# Generated by FakeRAM 2.0
VERSION 5.7 ;
BUSBITCHARS "[]" ;
PROPERTYDEFINITIONS
  MACRO width INTEGER ;
  MACRO depth INTEGER ;
  MACRO banks INTEGER ;
END PROPERTYDEFINITIONS
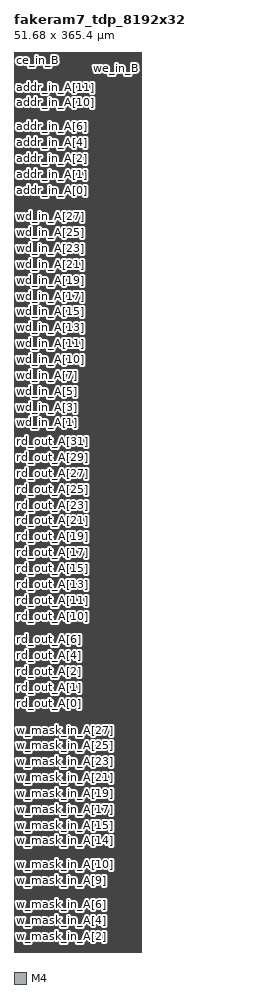
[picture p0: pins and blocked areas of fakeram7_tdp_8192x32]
MACRO fakeram7_tdp_8192x32
  PROPERTY width 32 ;
  PROPERTY depth 8192 ;
  PROPERTY banks 8 ;
  FOREIGN fakeram7_tdp_8192x32 0 0 ;
  SYMMETRY X Y ;
  SIZE 51.680 BY 365.400 ;
  CLASS BLOCK ;
  PIN w_mask_in_A[0]
    DIRECTION INPUT ;
    USE SIGNAL ;
    SHAPE ABUTMENT ;
    PORT
      LAYER M4 ;
      RECT 0.000 0.048 0.024 0.072 ;
    END
  END w_mask_in_A[0]
  PIN w_mask_in_B[0]
    DIRECTION INPUT ;
    USE SIGNAL ;
    SHAPE ABUTMENT ;
    PORT
      LAYER M4 ;
      RECT 51.656 0.048 51.680 0.072 ;
    END
  END w_mask_in_B[0]
  PIN w_mask_in_A[1]
    DIRECTION INPUT ;
    USE SIGNAL ;
    SHAPE ABUTMENT ;
    PORT
      LAYER M4 ;
      RECT 0.000 3.264 0.024 3.288 ;
    END
  END w_mask_in_A[1]
  PIN w_mask_in_B[1]
    DIRECTION INPUT ;
    USE SIGNAL ;
    SHAPE ABUTMENT ;
    PORT
      LAYER M4 ;
      RECT 51.656 3.264 51.680 3.288 ;
    END
  END w_mask_in_B[1]
  PIN w_mask_in_A[2]
    DIRECTION INPUT ;
    USE SIGNAL ;
    SHAPE ABUTMENT ;
    PORT
      LAYER M4 ;
      RECT 0.000 6.480 0.024 6.504 ;
    END
  END w_mask_in_A[2]
  PIN w_mask_in_B[2]
    DIRECTION INPUT ;
    USE SIGNAL ;
    SHAPE ABUTMENT ;
    PORT
      LAYER M4 ;
      RECT 51.656 6.480 51.680 6.504 ;
    END
  END w_mask_in_B[2]
  PIN w_mask_in_A[3]
    DIRECTION INPUT ;
    USE SIGNAL ;
    SHAPE ABUTMENT ;
    PORT
      LAYER M4 ;
      RECT 0.000 9.696 0.024 9.720 ;
    END
  END w_mask_in_A[3]
  PIN w_mask_in_B[3]
    DIRECTION INPUT ;
    USE SIGNAL ;
    SHAPE ABUTMENT ;
    PORT
      LAYER M4 ;
      RECT 51.656 9.696 51.680 9.720 ;
    END
  END w_mask_in_B[3]
  PIN w_mask_in_A[4]
    DIRECTION INPUT ;
    USE SIGNAL ;
    SHAPE ABUTMENT ;
    PORT
      LAYER M4 ;
      RECT 0.000 12.912 0.024 12.936 ;
    END
  END w_mask_in_A[4]
  PIN w_mask_in_B[4]
    DIRECTION INPUT ;
    USE SIGNAL ;
    SHAPE ABUTMENT ;
    PORT
      LAYER M4 ;
      RECT 51.656 12.912 51.680 12.936 ;
    END
  END w_mask_in_B[4]
  PIN w_mask_in_A[5]
    DIRECTION INPUT ;
    USE SIGNAL ;
    SHAPE ABUTMENT ;
    PORT
      LAYER M4 ;
      RECT 0.000 16.128 0.024 16.152 ;
    END
  END w_mask_in_A[5]
  PIN w_mask_in_B[5]
    DIRECTION INPUT ;
    USE SIGNAL ;
    SHAPE ABUTMENT ;
    PORT
      LAYER M4 ;
      RECT 51.656 16.128 51.680 16.152 ;
    END
  END w_mask_in_B[5]
  PIN w_mask_in_A[6]
    DIRECTION INPUT ;
    USE SIGNAL ;
    SHAPE ABUTMENT ;
    PORT
      LAYER M4 ;
      RECT 0.000 19.344 0.024 19.368 ;
    END
  END w_mask_in_A[6]
  PIN w_mask_in_B[6]
    DIRECTION INPUT ;
    USE SIGNAL ;
    SHAPE ABUTMENT ;
    PORT
      LAYER M4 ;
      RECT 51.656 19.344 51.680 19.368 ;
    END
  END w_mask_in_B[6]
  PIN w_mask_in_A[7]
    DIRECTION INPUT ;
    USE SIGNAL ;
    SHAPE ABUTMENT ;
    PORT
      LAYER M4 ;
      RECT 0.000 22.560 0.024 22.584 ;
    END
  END w_mask_in_A[7]
  PIN w_mask_in_B[7]
    DIRECTION INPUT ;
    USE SIGNAL ;
    SHAPE ABUTMENT ;
    PORT
      LAYER M4 ;
      RECT 51.656 22.560 51.680 22.584 ;
    END
  END w_mask_in_B[7]
  PIN w_mask_in_A[8]
    DIRECTION INPUT ;
    USE SIGNAL ;
    SHAPE ABUTMENT ;
    PORT
      LAYER M4 ;
      RECT 0.000 25.776 0.024 25.800 ;
    END
  END w_mask_in_A[8]
  PIN w_mask_in_B[8]
    DIRECTION INPUT ;
    USE SIGNAL ;
    SHAPE ABUTMENT ;
    PORT
      LAYER M4 ;
      RECT 51.656 25.776 51.680 25.800 ;
    END
  END w_mask_in_B[8]
  PIN w_mask_in_A[9]
    DIRECTION INPUT ;
    USE SIGNAL ;
    SHAPE ABUTMENT ;
    PORT
      LAYER M4 ;
      RECT 0.000 28.992 0.024 29.016 ;
    END
  END w_mask_in_A[9]
  PIN w_mask_in_B[9]
    DIRECTION INPUT ;
    USE SIGNAL ;
    SHAPE ABUTMENT ;
    PORT
      LAYER M4 ;
      RECT 51.656 28.992 51.680 29.016 ;
    END
  END w_mask_in_B[9]
  PIN w_mask_in_A[10]
    DIRECTION INPUT ;
    USE SIGNAL ;
    SHAPE ABUTMENT ;
    PORT
      LAYER M4 ;
      RECT 0.000 32.208 0.024 32.232 ;
    END
  END w_mask_in_A[10]
  PIN w_mask_in_B[10]
    DIRECTION INPUT ;
    USE SIGNAL ;
    SHAPE ABUTMENT ;
    PORT
      LAYER M4 ;
      RECT 51.656 32.208 51.680 32.232 ;
    END
  END w_mask_in_B[10]
  PIN w_mask_in_A[11]
    DIRECTION INPUT ;
    USE SIGNAL ;
    SHAPE ABUTMENT ;
    PORT
      LAYER M4 ;
      RECT 0.000 35.424 0.024 35.448 ;
    END
  END w_mask_in_A[11]
  PIN w_mask_in_B[11]
    DIRECTION INPUT ;
    USE SIGNAL ;
    SHAPE ABUTMENT ;
    PORT
      LAYER M4 ;
      RECT 51.656 35.424 51.680 35.448 ;
    END
  END w_mask_in_B[11]
  PIN w_mask_in_A[12]
    DIRECTION INPUT ;
    USE SIGNAL ;
    SHAPE ABUTMENT ;
    PORT
      LAYER M4 ;
      RECT 0.000 38.640 0.024 38.664 ;
    END
  END w_mask_in_A[12]
  PIN w_mask_in_B[12]
    DIRECTION INPUT ;
    USE SIGNAL ;
    SHAPE ABUTMENT ;
    PORT
      LAYER M4 ;
      RECT 51.656 38.640 51.680 38.664 ;
    END
  END w_mask_in_B[12]
  PIN w_mask_in_A[13]
    DIRECTION INPUT ;
    USE SIGNAL ;
    SHAPE ABUTMENT ;
    PORT
      LAYER M4 ;
      RECT 0.000 41.856 0.024 41.880 ;
    END
  END w_mask_in_A[13]
  PIN w_mask_in_B[13]
    DIRECTION INPUT ;
    USE SIGNAL ;
    SHAPE ABUTMENT ;
    PORT
      LAYER M4 ;
      RECT 51.656 41.856 51.680 41.880 ;
    END
  END w_mask_in_B[13]
  PIN w_mask_in_A[14]
    DIRECTION INPUT ;
    USE SIGNAL ;
    SHAPE ABUTMENT ;
    PORT
      LAYER M4 ;
      RECT 0.000 45.072 0.024 45.096 ;
    END
  END w_mask_in_A[14]
  PIN w_mask_in_B[14]
    DIRECTION INPUT ;
    USE SIGNAL ;
    SHAPE ABUTMENT ;
    PORT
      LAYER M4 ;
      RECT 51.656 45.072 51.680 45.096 ;
    END
  END w_mask_in_B[14]
  PIN w_mask_in_A[15]
    DIRECTION INPUT ;
    USE SIGNAL ;
    SHAPE ABUTMENT ;
    PORT
      LAYER M4 ;
      RECT 0.000 48.288 0.024 48.312 ;
    END
  END w_mask_in_A[15]
  PIN w_mask_in_B[15]
    DIRECTION INPUT ;
    USE SIGNAL ;
    SHAPE ABUTMENT ;
    PORT
      LAYER M4 ;
      RECT 51.656 48.288 51.680 48.312 ;
    END
  END w_mask_in_B[15]
  PIN w_mask_in_A[16]
    DIRECTION INPUT ;
    USE SIGNAL ;
    SHAPE ABUTMENT ;
    PORT
      LAYER M4 ;
      RECT 0.000 51.504 0.024 51.528 ;
    END
  END w_mask_in_A[16]
  PIN w_mask_in_B[16]
    DIRECTION INPUT ;
    USE SIGNAL ;
    SHAPE ABUTMENT ;
    PORT
      LAYER M4 ;
      RECT 51.656 51.504 51.680 51.528 ;
    END
  END w_mask_in_B[16]
  PIN w_mask_in_A[17]
    DIRECTION INPUT ;
    USE SIGNAL ;
    SHAPE ABUTMENT ;
    PORT
      LAYER M4 ;
      RECT 0.000 54.720 0.024 54.744 ;
    END
  END w_mask_in_A[17]
  PIN w_mask_in_B[17]
    DIRECTION INPUT ;
    USE SIGNAL ;
    SHAPE ABUTMENT ;
    PORT
      LAYER M4 ;
      RECT 51.656 54.720 51.680 54.744 ;
    END
  END w_mask_in_B[17]
  PIN w_mask_in_A[18]
    DIRECTION INPUT ;
    USE SIGNAL ;
    SHAPE ABUTMENT ;
    PORT
      LAYER M4 ;
      RECT 0.000 57.936 0.024 57.960 ;
    END
  END w_mask_in_A[18]
  PIN w_mask_in_B[18]
    DIRECTION INPUT ;
    USE SIGNAL ;
    SHAPE ABUTMENT ;
    PORT
      LAYER M4 ;
      RECT 51.656 57.936 51.680 57.960 ;
    END
  END w_mask_in_B[18]
  PIN w_mask_in_A[19]
    DIRECTION INPUT ;
    USE SIGNAL ;
    SHAPE ABUTMENT ;
    PORT
      LAYER M4 ;
      RECT 0.000 61.152 0.024 61.176 ;
    END
  END w_mask_in_A[19]
  PIN w_mask_in_B[19]
    DIRECTION INPUT ;
    USE SIGNAL ;
    SHAPE ABUTMENT ;
    PORT
      LAYER M4 ;
      RECT 51.656 61.152 51.680 61.176 ;
    END
  END w_mask_in_B[19]
  PIN w_mask_in_A[20]
    DIRECTION INPUT ;
    USE SIGNAL ;
    SHAPE ABUTMENT ;
    PORT
      LAYER M4 ;
      RECT 0.000 64.368 0.024 64.392 ;
    END
  END w_mask_in_A[20]
  PIN w_mask_in_B[20]
    DIRECTION INPUT ;
    USE SIGNAL ;
    SHAPE ABUTMENT ;
    PORT
      LAYER M4 ;
      RECT 51.656 64.368 51.680 64.392 ;
    END
  END w_mask_in_B[20]
  PIN w_mask_in_A[21]
    DIRECTION INPUT ;
    USE SIGNAL ;
    SHAPE ABUTMENT ;
    PORT
      LAYER M4 ;
      RECT 0.000 67.584 0.024 67.608 ;
    END
  END w_mask_in_A[21]
  PIN w_mask_in_B[21]
    DIRECTION INPUT ;
    USE SIGNAL ;
    SHAPE ABUTMENT ;
    PORT
      LAYER M4 ;
      RECT 51.656 67.584 51.680 67.608 ;
    END
  END w_mask_in_B[21]
  PIN w_mask_in_A[22]
    DIRECTION INPUT ;
    USE SIGNAL ;
    SHAPE ABUTMENT ;
    PORT
      LAYER M4 ;
      RECT 0.000 70.800 0.024 70.824 ;
    END
  END w_mask_in_A[22]
  PIN w_mask_in_B[22]
    DIRECTION INPUT ;
    USE SIGNAL ;
    SHAPE ABUTMENT ;
    PORT
      LAYER M4 ;
      RECT 51.656 70.800 51.680 70.824 ;
    END
  END w_mask_in_B[22]
  PIN w_mask_in_A[23]
    DIRECTION INPUT ;
    USE SIGNAL ;
    SHAPE ABUTMENT ;
    PORT
      LAYER M4 ;
      RECT 0.000 74.016 0.024 74.040 ;
    END
  END w_mask_in_A[23]
  PIN w_mask_in_B[23]
    DIRECTION INPUT ;
    USE SIGNAL ;
    SHAPE ABUTMENT ;
    PORT
      LAYER M4 ;
      RECT 51.656 74.016 51.680 74.040 ;
    END
  END w_mask_in_B[23]
  PIN w_mask_in_A[24]
    DIRECTION INPUT ;
    USE SIGNAL ;
    SHAPE ABUTMENT ;
    PORT
      LAYER M4 ;
      RECT 0.000 77.232 0.024 77.256 ;
    END
  END w_mask_in_A[24]
  PIN w_mask_in_B[24]
    DIRECTION INPUT ;
    USE SIGNAL ;
    SHAPE ABUTMENT ;
    PORT
      LAYER M4 ;
      RECT 51.656 77.232 51.680 77.256 ;
    END
  END w_mask_in_B[24]
  PIN w_mask_in_A[25]
    DIRECTION INPUT ;
    USE SIGNAL ;
    SHAPE ABUTMENT ;
    PORT
      LAYER M4 ;
      RECT 0.000 80.448 0.024 80.472 ;
    END
  END w_mask_in_A[25]
  PIN w_mask_in_B[25]
    DIRECTION INPUT ;
    USE SIGNAL ;
    SHAPE ABUTMENT ;
    PORT
      LAYER M4 ;
      RECT 51.656 80.448 51.680 80.472 ;
    END
  END w_mask_in_B[25]
  PIN w_mask_in_A[26]
    DIRECTION INPUT ;
    USE SIGNAL ;
    SHAPE ABUTMENT ;
    PORT
      LAYER M4 ;
      RECT 0.000 83.664 0.024 83.688 ;
    END
  END w_mask_in_A[26]
  PIN w_mask_in_B[26]
    DIRECTION INPUT ;
    USE SIGNAL ;
    SHAPE ABUTMENT ;
    PORT
      LAYER M4 ;
      RECT 51.656 83.664 51.680 83.688 ;
    END
  END w_mask_in_B[26]
  PIN w_mask_in_A[27]
    DIRECTION INPUT ;
    USE SIGNAL ;
    SHAPE ABUTMENT ;
    PORT
      LAYER M4 ;
      RECT 0.000 86.880 0.024 86.904 ;
    END
  END w_mask_in_A[27]
  PIN w_mask_in_B[27]
    DIRECTION INPUT ;
    USE SIGNAL ;
    SHAPE ABUTMENT ;
    PORT
      LAYER M4 ;
      RECT 51.656 86.880 51.680 86.904 ;
    END
  END w_mask_in_B[27]
  PIN w_mask_in_A[28]
    DIRECTION INPUT ;
    USE SIGNAL ;
    SHAPE ABUTMENT ;
    PORT
      LAYER M4 ;
      RECT 0.000 90.096 0.024 90.120 ;
    END
  END w_mask_in_A[28]
  PIN w_mask_in_B[28]
    DIRECTION INPUT ;
    USE SIGNAL ;
    SHAPE ABUTMENT ;
    PORT
      LAYER M4 ;
      RECT 51.656 90.096 51.680 90.120 ;
    END
  END w_mask_in_B[28]
  PIN w_mask_in_A[29]
    DIRECTION INPUT ;
    USE SIGNAL ;
    SHAPE ABUTMENT ;
    PORT
      LAYER M4 ;
      RECT 0.000 93.312 0.024 93.336 ;
    END
  END w_mask_in_A[29]
  PIN w_mask_in_B[29]
    DIRECTION INPUT ;
    USE SIGNAL ;
    SHAPE ABUTMENT ;
    PORT
      LAYER M4 ;
      RECT 51.656 93.312 51.680 93.336 ;
    END
  END w_mask_in_B[29]
  PIN w_mask_in_A[30]
    DIRECTION INPUT ;
    USE SIGNAL ;
    SHAPE ABUTMENT ;
    PORT
      LAYER M4 ;
      RECT 0.000 96.528 0.024 96.552 ;
    END
  END w_mask_in_A[30]
  PIN w_mask_in_B[30]
    DIRECTION INPUT ;
    USE SIGNAL ;
    SHAPE ABUTMENT ;
    PORT
      LAYER M4 ;
      RECT 51.656 96.528 51.680 96.552 ;
    END
  END w_mask_in_B[30]
  PIN w_mask_in_A[31]
    DIRECTION INPUT ;
    USE SIGNAL ;
    SHAPE ABUTMENT ;
    PORT
      LAYER M4 ;
      RECT 0.000 99.744 0.024 99.768 ;
    END
  END w_mask_in_A[31]
  PIN w_mask_in_B[31]
    DIRECTION INPUT ;
    USE SIGNAL ;
    SHAPE ABUTMENT ;
    PORT
      LAYER M4 ;
      RECT 51.656 99.744 51.680 99.768 ;
    END
  END w_mask_in_B[31]
  PIN rd_out_A[0]
    DIRECTION OUTPUT ;
    USE SIGNAL ;
    SHAPE ABUTMENT ;
    PORT
      LAYER M4 ;
      RECT 0.000 104.208 0.024 104.232 ;
    END
  END rd_out_A[0]
  PIN rd_out_B[0]
    DIRECTION OUTPUT ;
    USE SIGNAL ;
    SHAPE ABUTMENT ;
    PORT
      LAYER M4 ;
      RECT 51.656 104.208 51.680 104.232 ;
    END
  END rd_out_B[0]
  PIN rd_out_A[1]
    DIRECTION OUTPUT ;
    USE SIGNAL ;
    SHAPE ABUTMENT ;
    PORT
      LAYER M4 ;
      RECT 0.000 107.424 0.024 107.448 ;
    END
  END rd_out_A[1]
  PIN rd_out_B[1]
    DIRECTION OUTPUT ;
    USE SIGNAL ;
    SHAPE ABUTMENT ;
    PORT
      LAYER M4 ;
      RECT 51.656 107.424 51.680 107.448 ;
    END
  END rd_out_B[1]
  PIN rd_out_A[2]
    DIRECTION OUTPUT ;
    USE SIGNAL ;
    SHAPE ABUTMENT ;
    PORT
      LAYER M4 ;
      RECT 0.000 110.640 0.024 110.664 ;
    END
  END rd_out_A[2]
  PIN rd_out_B[2]
    DIRECTION OUTPUT ;
    USE SIGNAL ;
    SHAPE ABUTMENT ;
    PORT
      LAYER M4 ;
      RECT 51.656 110.640 51.680 110.664 ;
    END
  END rd_out_B[2]
  PIN rd_out_A[3]
    DIRECTION OUTPUT ;
    USE SIGNAL ;
    SHAPE ABUTMENT ;
    PORT
      LAYER M4 ;
      RECT 0.000 113.856 0.024 113.880 ;
    END
  END rd_out_A[3]
  PIN rd_out_B[3]
    DIRECTION OUTPUT ;
    USE SIGNAL ;
    SHAPE ABUTMENT ;
    PORT
      LAYER M4 ;
      RECT 51.656 113.856 51.680 113.880 ;
    END
  END rd_out_B[3]
  PIN rd_out_A[4]
    DIRECTION OUTPUT ;
    USE SIGNAL ;
    SHAPE ABUTMENT ;
    PORT
      LAYER M4 ;
      RECT 0.000 117.072 0.024 117.096 ;
    END
  END rd_out_A[4]
  PIN rd_out_B[4]
    DIRECTION OUTPUT ;
    USE SIGNAL ;
    SHAPE ABUTMENT ;
    PORT
      LAYER M4 ;
      RECT 51.656 117.072 51.680 117.096 ;
    END
  END rd_out_B[4]
  PIN rd_out_A[5]
    DIRECTION OUTPUT ;
    USE SIGNAL ;
    SHAPE ABUTMENT ;
    PORT
      LAYER M4 ;
      RECT 0.000 120.288 0.024 120.312 ;
    END
  END rd_out_A[5]
  PIN rd_out_B[5]
    DIRECTION OUTPUT ;
    USE SIGNAL ;
    SHAPE ABUTMENT ;
    PORT
      LAYER M4 ;
      RECT 51.656 120.288 51.680 120.312 ;
    END
  END rd_out_B[5]
  PIN rd_out_A[6]
    DIRECTION OUTPUT ;
    USE SIGNAL ;
    SHAPE ABUTMENT ;
    PORT
      LAYER M4 ;
      RECT 0.000 123.504 0.024 123.528 ;
    END
  END rd_out_A[6]
  PIN rd_out_B[6]
    DIRECTION OUTPUT ;
    USE SIGNAL ;
    SHAPE ABUTMENT ;
    PORT
      LAYER M4 ;
      RECT 51.656 123.504 51.680 123.528 ;
    END
  END rd_out_B[6]
  PIN rd_out_A[7]
    DIRECTION OUTPUT ;
    USE SIGNAL ;
    SHAPE ABUTMENT ;
    PORT
      LAYER M4 ;
      RECT 0.000 126.720 0.024 126.744 ;
    END
  END rd_out_A[7]
  PIN rd_out_B[7]
    DIRECTION OUTPUT ;
    USE SIGNAL ;
    SHAPE ABUTMENT ;
    PORT
      LAYER M4 ;
      RECT 51.656 126.720 51.680 126.744 ;
    END
  END rd_out_B[7]
  PIN rd_out_A[8]
    DIRECTION OUTPUT ;
    USE SIGNAL ;
    SHAPE ABUTMENT ;
    PORT
      LAYER M4 ;
      RECT 0.000 129.936 0.024 129.960 ;
    END
  END rd_out_A[8]
  PIN rd_out_B[8]
    DIRECTION OUTPUT ;
    USE SIGNAL ;
    SHAPE ABUTMENT ;
    PORT
      LAYER M4 ;
      RECT 51.656 129.936 51.680 129.960 ;
    END
  END rd_out_B[8]
  PIN rd_out_A[9]
    DIRECTION OUTPUT ;
    USE SIGNAL ;
    SHAPE ABUTMENT ;
    PORT
      LAYER M4 ;
      RECT 0.000 133.152 0.024 133.176 ;
    END
  END rd_out_A[9]
  PIN rd_out_B[9]
    DIRECTION OUTPUT ;
    USE SIGNAL ;
    SHAPE ABUTMENT ;
    PORT
      LAYER M4 ;
      RECT 51.656 133.152 51.680 133.176 ;
    END
  END rd_out_B[9]
  PIN rd_out_A[10]
    DIRECTION OUTPUT ;
    USE SIGNAL ;
    SHAPE ABUTMENT ;
    PORT
      LAYER M4 ;
      RECT 0.000 136.368 0.024 136.392 ;
    END
  END rd_out_A[10]
  PIN rd_out_B[10]
    DIRECTION OUTPUT ;
    USE SIGNAL ;
    SHAPE ABUTMENT ;
    PORT
      LAYER M4 ;
      RECT 51.656 136.368 51.680 136.392 ;
    END
  END rd_out_B[10]
  PIN rd_out_A[11]
    DIRECTION OUTPUT ;
    USE SIGNAL ;
    SHAPE ABUTMENT ;
    PORT
      LAYER M4 ;
      RECT 0.000 139.584 0.024 139.608 ;
    END
  END rd_out_A[11]
  PIN rd_out_B[11]
    DIRECTION OUTPUT ;
    USE SIGNAL ;
    SHAPE ABUTMENT ;
    PORT
      LAYER M4 ;
      RECT 51.656 139.584 51.680 139.608 ;
    END
  END rd_out_B[11]
  PIN rd_out_A[12]
    DIRECTION OUTPUT ;
    USE SIGNAL ;
    SHAPE ABUTMENT ;
    PORT
      LAYER M4 ;
      RECT 0.000 142.800 0.024 142.824 ;
    END
  END rd_out_A[12]
  PIN rd_out_B[12]
    DIRECTION OUTPUT ;
    USE SIGNAL ;
    SHAPE ABUTMENT ;
    PORT
      LAYER M4 ;
      RECT 51.656 142.800 51.680 142.824 ;
    END
  END rd_out_B[12]
  PIN rd_out_A[13]
    DIRECTION OUTPUT ;
    USE SIGNAL ;
    SHAPE ABUTMENT ;
    PORT
      LAYER M4 ;
      RECT 0.000 146.016 0.024 146.040 ;
    END
  END rd_out_A[13]
  PIN rd_out_B[13]
    DIRECTION OUTPUT ;
    USE SIGNAL ;
    SHAPE ABUTMENT ;
    PORT
      LAYER M4 ;
      RECT 51.656 146.016 51.680 146.040 ;
    END
  END rd_out_B[13]
  PIN rd_out_A[14]
    DIRECTION OUTPUT ;
    USE SIGNAL ;
    SHAPE ABUTMENT ;
    PORT
      LAYER M4 ;
      RECT 0.000 149.232 0.024 149.256 ;
    END
  END rd_out_A[14]
  PIN rd_out_B[14]
    DIRECTION OUTPUT ;
    USE SIGNAL ;
    SHAPE ABUTMENT ;
    PORT
      LAYER M4 ;
      RECT 51.656 149.232 51.680 149.256 ;
    END
  END rd_out_B[14]
  PIN rd_out_A[15]
    DIRECTION OUTPUT ;
    USE SIGNAL ;
    SHAPE ABUTMENT ;
    PORT
      LAYER M4 ;
      RECT 0.000 152.448 0.024 152.472 ;
    END
  END rd_out_A[15]
  PIN rd_out_B[15]
    DIRECTION OUTPUT ;
    USE SIGNAL ;
    SHAPE ABUTMENT ;
    PORT
      LAYER M4 ;
      RECT 51.656 152.448 51.680 152.472 ;
    END
  END rd_out_B[15]
  PIN rd_out_A[16]
    DIRECTION OUTPUT ;
    USE SIGNAL ;
    SHAPE ABUTMENT ;
    PORT
      LAYER M4 ;
      RECT 0.000 155.664 0.024 155.688 ;
    END
  END rd_out_A[16]
  PIN rd_out_B[16]
    DIRECTION OUTPUT ;
    USE SIGNAL ;
    SHAPE ABUTMENT ;
    PORT
      LAYER M4 ;
      RECT 51.656 155.664 51.680 155.688 ;
    END
  END rd_out_B[16]
  PIN rd_out_A[17]
    DIRECTION OUTPUT ;
    USE SIGNAL ;
    SHAPE ABUTMENT ;
    PORT
      LAYER M4 ;
      RECT 0.000 158.880 0.024 158.904 ;
    END
  END rd_out_A[17]
  PIN rd_out_B[17]
    DIRECTION OUTPUT ;
    USE SIGNAL ;
    SHAPE ABUTMENT ;
    PORT
      LAYER M4 ;
      RECT 51.656 158.880 51.680 158.904 ;
    END
  END rd_out_B[17]
  PIN rd_out_A[18]
    DIRECTION OUTPUT ;
    USE SIGNAL ;
    SHAPE ABUTMENT ;
    PORT
      LAYER M4 ;
      RECT 0.000 162.096 0.024 162.120 ;
    END
  END rd_out_A[18]
  PIN rd_out_B[18]
    DIRECTION OUTPUT ;
    USE SIGNAL ;
    SHAPE ABUTMENT ;
    PORT
      LAYER M4 ;
      RECT 51.656 162.096 51.680 162.120 ;
    END
  END rd_out_B[18]
  PIN rd_out_A[19]
    DIRECTION OUTPUT ;
    USE SIGNAL ;
    SHAPE ABUTMENT ;
    PORT
      LAYER M4 ;
      RECT 0.000 165.312 0.024 165.336 ;
    END
  END rd_out_A[19]
  PIN rd_out_B[19]
    DIRECTION OUTPUT ;
    USE SIGNAL ;
    SHAPE ABUTMENT ;
    PORT
      LAYER M4 ;
      RECT 51.656 165.312 51.680 165.336 ;
    END
  END rd_out_B[19]
  PIN rd_out_A[20]
    DIRECTION OUTPUT ;
    USE SIGNAL ;
    SHAPE ABUTMENT ;
    PORT
      LAYER M4 ;
      RECT 0.000 168.528 0.024 168.552 ;
    END
  END rd_out_A[20]
  PIN rd_out_B[20]
    DIRECTION OUTPUT ;
    USE SIGNAL ;
    SHAPE ABUTMENT ;
    PORT
      LAYER M4 ;
      RECT 51.656 168.528 51.680 168.552 ;
    END
  END rd_out_B[20]
  PIN rd_out_A[21]
    DIRECTION OUTPUT ;
    USE SIGNAL ;
    SHAPE ABUTMENT ;
    PORT
      LAYER M4 ;
      RECT 0.000 171.744 0.024 171.768 ;
    END
  END rd_out_A[21]
  PIN rd_out_B[21]
    DIRECTION OUTPUT ;
    USE SIGNAL ;
    SHAPE ABUTMENT ;
    PORT
      LAYER M4 ;
      RECT 51.656 171.744 51.680 171.768 ;
    END
  END rd_out_B[21]
  PIN rd_out_A[22]
    DIRECTION OUTPUT ;
    USE SIGNAL ;
    SHAPE ABUTMENT ;
    PORT
      LAYER M4 ;
      RECT 0.000 174.960 0.024 174.984 ;
    END
  END rd_out_A[22]
  PIN rd_out_B[22]
    DIRECTION OUTPUT ;
    USE SIGNAL ;
    SHAPE ABUTMENT ;
    PORT
      LAYER M4 ;
      RECT 51.656 174.960 51.680 174.984 ;
    END
  END rd_out_B[22]
  PIN rd_out_A[23]
    DIRECTION OUTPUT ;
    USE SIGNAL ;
    SHAPE ABUTMENT ;
    PORT
      LAYER M4 ;
      RECT 0.000 178.176 0.024 178.200 ;
    END
  END rd_out_A[23]
  PIN rd_out_B[23]
    DIRECTION OUTPUT ;
    USE SIGNAL ;
    SHAPE ABUTMENT ;
    PORT
      LAYER M4 ;
      RECT 51.656 178.176 51.680 178.200 ;
    END
  END rd_out_B[23]
  PIN rd_out_A[24]
    DIRECTION OUTPUT ;
    USE SIGNAL ;
    SHAPE ABUTMENT ;
    PORT
      LAYER M4 ;
      RECT 0.000 181.392 0.024 181.416 ;
    END
  END rd_out_A[24]
  PIN rd_out_B[24]
    DIRECTION OUTPUT ;
    USE SIGNAL ;
    SHAPE ABUTMENT ;
    PORT
      LAYER M4 ;
      RECT 51.656 181.392 51.680 181.416 ;
    END
  END rd_out_B[24]
  PIN rd_out_A[25]
    DIRECTION OUTPUT ;
    USE SIGNAL ;
    SHAPE ABUTMENT ;
    PORT
      LAYER M4 ;
      RECT 0.000 184.608 0.024 184.632 ;
    END
  END rd_out_A[25]
  PIN rd_out_B[25]
    DIRECTION OUTPUT ;
    USE SIGNAL ;
    SHAPE ABUTMENT ;
    PORT
      LAYER M4 ;
      RECT 51.656 184.608 51.680 184.632 ;
    END
  END rd_out_B[25]
  PIN rd_out_A[26]
    DIRECTION OUTPUT ;
    USE SIGNAL ;
    SHAPE ABUTMENT ;
    PORT
      LAYER M4 ;
      RECT 0.000 187.824 0.024 187.848 ;
    END
  END rd_out_A[26]
  PIN rd_out_B[26]
    DIRECTION OUTPUT ;
    USE SIGNAL ;
    SHAPE ABUTMENT ;
    PORT
      LAYER M4 ;
      RECT 51.656 187.824 51.680 187.848 ;
    END
  END rd_out_B[26]
  PIN rd_out_A[27]
    DIRECTION OUTPUT ;
    USE SIGNAL ;
    SHAPE ABUTMENT ;
    PORT
      LAYER M4 ;
      RECT 0.000 191.040 0.024 191.064 ;
    END
  END rd_out_A[27]
  PIN rd_out_B[27]
    DIRECTION OUTPUT ;
    USE SIGNAL ;
    SHAPE ABUTMENT ;
    PORT
      LAYER M4 ;
      RECT 51.656 191.040 51.680 191.064 ;
    END
  END rd_out_B[27]
  PIN rd_out_A[28]
    DIRECTION OUTPUT ;
    USE SIGNAL ;
    SHAPE ABUTMENT ;
    PORT
      LAYER M4 ;
      RECT 0.000 194.256 0.024 194.280 ;
    END
  END rd_out_A[28]
  PIN rd_out_B[28]
    DIRECTION OUTPUT ;
    USE SIGNAL ;
    SHAPE ABUTMENT ;
    PORT
      LAYER M4 ;
      RECT 51.656 194.256 51.680 194.280 ;
    END
  END rd_out_B[28]
  PIN rd_out_A[29]
    DIRECTION OUTPUT ;
    USE SIGNAL ;
    SHAPE ABUTMENT ;
    PORT
      LAYER M4 ;
      RECT 0.000 197.472 0.024 197.496 ;
    END
  END rd_out_A[29]
  PIN rd_out_B[29]
    DIRECTION OUTPUT ;
    USE SIGNAL ;
    SHAPE ABUTMENT ;
    PORT
      LAYER M4 ;
      RECT 51.656 197.472 51.680 197.496 ;
    END
  END rd_out_B[29]
  PIN rd_out_A[30]
    DIRECTION OUTPUT ;
    USE SIGNAL ;
    SHAPE ABUTMENT ;
    PORT
      LAYER M4 ;
      RECT 0.000 200.688 0.024 200.712 ;
    END
  END rd_out_A[30]
  PIN rd_out_B[30]
    DIRECTION OUTPUT ;
    USE SIGNAL ;
    SHAPE ABUTMENT ;
    PORT
      LAYER M4 ;
      RECT 51.656 200.688 51.680 200.712 ;
    END
  END rd_out_B[30]
  PIN rd_out_A[31]
    DIRECTION OUTPUT ;
    USE SIGNAL ;
    SHAPE ABUTMENT ;
    PORT
      LAYER M4 ;
      RECT 0.000 203.904 0.024 203.928 ;
    END
  END rd_out_A[31]
  PIN rd_out_B[31]
    DIRECTION OUTPUT ;
    USE SIGNAL ;
    SHAPE ABUTMENT ;
    PORT
      LAYER M4 ;
      RECT 51.656 203.904 51.680 203.928 ;
    END
  END rd_out_B[31]
  PIN wd_in_A[0]
    DIRECTION INPUT ;
    USE SIGNAL ;
    SHAPE ABUTMENT ;
    PORT
      LAYER M4 ;
      RECT 0.000 208.368 0.024 208.392 ;
    END
  END wd_in_A[0]
  PIN wd_in_B[0]
    DIRECTION INPUT ;
    USE SIGNAL ;
    SHAPE ABUTMENT ;
    PORT
      LAYER M4 ;
      RECT 51.656 208.368 51.680 208.392 ;
    END
  END wd_in_B[0]
  PIN wd_in_A[1]
    DIRECTION INPUT ;
    USE SIGNAL ;
    SHAPE ABUTMENT ;
    PORT
      LAYER M4 ;
      RECT 0.000 211.584 0.024 211.608 ;
    END
  END wd_in_A[1]
  PIN wd_in_B[1]
    DIRECTION INPUT ;
    USE SIGNAL ;
    SHAPE ABUTMENT ;
    PORT
      LAYER M4 ;
      RECT 51.656 211.584 51.680 211.608 ;
    END
  END wd_in_B[1]
  PIN wd_in_A[2]
    DIRECTION INPUT ;
    USE SIGNAL ;
    SHAPE ABUTMENT ;
    PORT
      LAYER M4 ;
      RECT 0.000 214.800 0.024 214.824 ;
    END
  END wd_in_A[2]
  PIN wd_in_B[2]
    DIRECTION INPUT ;
    USE SIGNAL ;
    SHAPE ABUTMENT ;
    PORT
      LAYER M4 ;
      RECT 51.656 214.800 51.680 214.824 ;
    END
  END wd_in_B[2]
  PIN wd_in_A[3]
    DIRECTION INPUT ;
    USE SIGNAL ;
    SHAPE ABUTMENT ;
    PORT
      LAYER M4 ;
      RECT 0.000 218.016 0.024 218.040 ;
    END
  END wd_in_A[3]
  PIN wd_in_B[3]
    DIRECTION INPUT ;
    USE SIGNAL ;
    SHAPE ABUTMENT ;
    PORT
      LAYER M4 ;
      RECT 51.656 218.016 51.680 218.040 ;
    END
  END wd_in_B[3]
  PIN wd_in_A[4]
    DIRECTION INPUT ;
    USE SIGNAL ;
    SHAPE ABUTMENT ;
    PORT
      LAYER M4 ;
      RECT 0.000 221.232 0.024 221.256 ;
    END
  END wd_in_A[4]
  PIN wd_in_B[4]
    DIRECTION INPUT ;
    USE SIGNAL ;
    SHAPE ABUTMENT ;
    PORT
      LAYER M4 ;
      RECT 51.656 221.232 51.680 221.256 ;
    END
  END wd_in_B[4]
  PIN wd_in_A[5]
    DIRECTION INPUT ;
    USE SIGNAL ;
    SHAPE ABUTMENT ;
    PORT
      LAYER M4 ;
      RECT 0.000 224.448 0.024 224.472 ;
    END
  END wd_in_A[5]
  PIN wd_in_B[5]
    DIRECTION INPUT ;
    USE SIGNAL ;
    SHAPE ABUTMENT ;
    PORT
      LAYER M4 ;
      RECT 51.656 224.448 51.680 224.472 ;
    END
  END wd_in_B[5]
  PIN wd_in_A[6]
    DIRECTION INPUT ;
    USE SIGNAL ;
    SHAPE ABUTMENT ;
    PORT
      LAYER M4 ;
      RECT 0.000 227.664 0.024 227.688 ;
    END
  END wd_in_A[6]
  PIN wd_in_B[6]
    DIRECTION INPUT ;
    USE SIGNAL ;
    SHAPE ABUTMENT ;
    PORT
      LAYER M4 ;
      RECT 51.656 227.664 51.680 227.688 ;
    END
  END wd_in_B[6]
  PIN wd_in_A[7]
    DIRECTION INPUT ;
    USE SIGNAL ;
    SHAPE ABUTMENT ;
    PORT
      LAYER M4 ;
      RECT 0.000 230.880 0.024 230.904 ;
    END
  END wd_in_A[7]
  PIN wd_in_B[7]
    DIRECTION INPUT ;
    USE SIGNAL ;
    SHAPE ABUTMENT ;
    PORT
      LAYER M4 ;
      RECT 51.656 230.880 51.680 230.904 ;
    END
  END wd_in_B[7]
  PIN wd_in_A[8]
    DIRECTION INPUT ;
    USE SIGNAL ;
    SHAPE ABUTMENT ;
    PORT
      LAYER M4 ;
      RECT 0.000 234.096 0.024 234.120 ;
    END
  END wd_in_A[8]
  PIN wd_in_B[8]
    DIRECTION INPUT ;
    USE SIGNAL ;
    SHAPE ABUTMENT ;
    PORT
      LAYER M4 ;
      RECT 51.656 234.096 51.680 234.120 ;
    END
  END wd_in_B[8]
  PIN wd_in_A[9]
    DIRECTION INPUT ;
    USE SIGNAL ;
    SHAPE ABUTMENT ;
    PORT
      LAYER M4 ;
      RECT 0.000 237.312 0.024 237.336 ;
    END
  END wd_in_A[9]
  PIN wd_in_B[9]
    DIRECTION INPUT ;
    USE SIGNAL ;
    SHAPE ABUTMENT ;
    PORT
      LAYER M4 ;
      RECT 51.656 237.312 51.680 237.336 ;
    END
  END wd_in_B[9]
  PIN wd_in_A[10]
    DIRECTION INPUT ;
    USE SIGNAL ;
    SHAPE ABUTMENT ;
    PORT
      LAYER M4 ;
      RECT 0.000 240.528 0.024 240.552 ;
    END
  END wd_in_A[10]
  PIN wd_in_B[10]
    DIRECTION INPUT ;
    USE SIGNAL ;
    SHAPE ABUTMENT ;
    PORT
      LAYER M4 ;
      RECT 51.656 240.528 51.680 240.552 ;
    END
  END wd_in_B[10]
  PIN wd_in_A[11]
    DIRECTION INPUT ;
    USE SIGNAL ;
    SHAPE ABUTMENT ;
    PORT
      LAYER M4 ;
      RECT 0.000 243.744 0.024 243.768 ;
    END
  END wd_in_A[11]
  PIN wd_in_B[11]
    DIRECTION INPUT ;
    USE SIGNAL ;
    SHAPE ABUTMENT ;
    PORT
      LAYER M4 ;
      RECT 51.656 243.744 51.680 243.768 ;
    END
  END wd_in_B[11]
  PIN wd_in_A[12]
    DIRECTION INPUT ;
    USE SIGNAL ;
    SHAPE ABUTMENT ;
    PORT
      LAYER M4 ;
      RECT 0.000 246.960 0.024 246.984 ;
    END
  END wd_in_A[12]
  PIN wd_in_B[12]
    DIRECTION INPUT ;
    USE SIGNAL ;
    SHAPE ABUTMENT ;
    PORT
      LAYER M4 ;
      RECT 51.656 246.960 51.680 246.984 ;
    END
  END wd_in_B[12]
  PIN wd_in_A[13]
    DIRECTION INPUT ;
    USE SIGNAL ;
    SHAPE ABUTMENT ;
    PORT
      LAYER M4 ;
      RECT 0.000 250.176 0.024 250.200 ;
    END
  END wd_in_A[13]
  PIN wd_in_B[13]
    DIRECTION INPUT ;
    USE SIGNAL ;
    SHAPE ABUTMENT ;
    PORT
      LAYER M4 ;
      RECT 51.656 250.176 51.680 250.200 ;
    END
  END wd_in_B[13]
  PIN wd_in_A[14]
    DIRECTION INPUT ;
    USE SIGNAL ;
    SHAPE ABUTMENT ;
    PORT
      LAYER M4 ;
      RECT 0.000 253.392 0.024 253.416 ;
    END
  END wd_in_A[14]
  PIN wd_in_B[14]
    DIRECTION INPUT ;
    USE SIGNAL ;
    SHAPE ABUTMENT ;
    PORT
      LAYER M4 ;
      RECT 51.656 253.392 51.680 253.416 ;
    END
  END wd_in_B[14]
  PIN wd_in_A[15]
    DIRECTION INPUT ;
    USE SIGNAL ;
    SHAPE ABUTMENT ;
    PORT
      LAYER M4 ;
      RECT 0.000 256.608 0.024 256.632 ;
    END
  END wd_in_A[15]
  PIN wd_in_B[15]
    DIRECTION INPUT ;
    USE SIGNAL ;
    SHAPE ABUTMENT ;
    PORT
      LAYER M4 ;
      RECT 51.656 256.608 51.680 256.632 ;
    END
  END wd_in_B[15]
  PIN wd_in_A[16]
    DIRECTION INPUT ;
    USE SIGNAL ;
    SHAPE ABUTMENT ;
    PORT
      LAYER M4 ;
      RECT 0.000 259.824 0.024 259.848 ;
    END
  END wd_in_A[16]
  PIN wd_in_B[16]
    DIRECTION INPUT ;
    USE SIGNAL ;
    SHAPE ABUTMENT ;
    PORT
      LAYER M4 ;
      RECT 51.656 259.824 51.680 259.848 ;
    END
  END wd_in_B[16]
  PIN wd_in_A[17]
    DIRECTION INPUT ;
    USE SIGNAL ;
    SHAPE ABUTMENT ;
    PORT
      LAYER M4 ;
      RECT 0.000 263.040 0.024 263.064 ;
    END
  END wd_in_A[17]
  PIN wd_in_B[17]
    DIRECTION INPUT ;
    USE SIGNAL ;
    SHAPE ABUTMENT ;
    PORT
      LAYER M4 ;
      RECT 51.656 263.040 51.680 263.064 ;
    END
  END wd_in_B[17]
  PIN wd_in_A[18]
    DIRECTION INPUT ;
    USE SIGNAL ;
    SHAPE ABUTMENT ;
    PORT
      LAYER M4 ;
      RECT 0.000 266.256 0.024 266.280 ;
    END
  END wd_in_A[18]
  PIN wd_in_B[18]
    DIRECTION INPUT ;
    USE SIGNAL ;
    SHAPE ABUTMENT ;
    PORT
      LAYER M4 ;
      RECT 51.656 266.256 51.680 266.280 ;
    END
  END wd_in_B[18]
  PIN wd_in_A[19]
    DIRECTION INPUT ;
    USE SIGNAL ;
    SHAPE ABUTMENT ;
    PORT
      LAYER M4 ;
      RECT 0.000 269.472 0.024 269.496 ;
    END
  END wd_in_A[19]
  PIN wd_in_B[19]
    DIRECTION INPUT ;
    USE SIGNAL ;
    SHAPE ABUTMENT ;
    PORT
      LAYER M4 ;
      RECT 51.656 269.472 51.680 269.496 ;
    END
  END wd_in_B[19]
  PIN wd_in_A[20]
    DIRECTION INPUT ;
    USE SIGNAL ;
    SHAPE ABUTMENT ;
    PORT
      LAYER M4 ;
      RECT 0.000 272.688 0.024 272.712 ;
    END
  END wd_in_A[20]
  PIN wd_in_B[20]
    DIRECTION INPUT ;
    USE SIGNAL ;
    SHAPE ABUTMENT ;
    PORT
      LAYER M4 ;
      RECT 51.656 272.688 51.680 272.712 ;
    END
  END wd_in_B[20]
  PIN wd_in_A[21]
    DIRECTION INPUT ;
    USE SIGNAL ;
    SHAPE ABUTMENT ;
    PORT
      LAYER M4 ;
      RECT 0.000 275.904 0.024 275.928 ;
    END
  END wd_in_A[21]
  PIN wd_in_B[21]
    DIRECTION INPUT ;
    USE SIGNAL ;
    SHAPE ABUTMENT ;
    PORT
      LAYER M4 ;
      RECT 51.656 275.904 51.680 275.928 ;
    END
  END wd_in_B[21]
  PIN wd_in_A[22]
    DIRECTION INPUT ;
    USE SIGNAL ;
    SHAPE ABUTMENT ;
    PORT
      LAYER M4 ;
      RECT 0.000 279.120 0.024 279.144 ;
    END
  END wd_in_A[22]
  PIN wd_in_B[22]
    DIRECTION INPUT ;
    USE SIGNAL ;
    SHAPE ABUTMENT ;
    PORT
      LAYER M4 ;
      RECT 51.656 279.120 51.680 279.144 ;
    END
  END wd_in_B[22]
  PIN wd_in_A[23]
    DIRECTION INPUT ;
    USE SIGNAL ;
    SHAPE ABUTMENT ;
    PORT
      LAYER M4 ;
      RECT 0.000 282.336 0.024 282.360 ;
    END
  END wd_in_A[23]
  PIN wd_in_B[23]
    DIRECTION INPUT ;
    USE SIGNAL ;
    SHAPE ABUTMENT ;
    PORT
      LAYER M4 ;
      RECT 51.656 282.336 51.680 282.360 ;
    END
  END wd_in_B[23]
  PIN wd_in_A[24]
    DIRECTION INPUT ;
    USE SIGNAL ;
    SHAPE ABUTMENT ;
    PORT
      LAYER M4 ;
      RECT 0.000 285.552 0.024 285.576 ;
    END
  END wd_in_A[24]
  PIN wd_in_B[24]
    DIRECTION INPUT ;
    USE SIGNAL ;
    SHAPE ABUTMENT ;
    PORT
      LAYER M4 ;
      RECT 51.656 285.552 51.680 285.576 ;
    END
  END wd_in_B[24]
  PIN wd_in_A[25]
    DIRECTION INPUT ;
    USE SIGNAL ;
    SHAPE ABUTMENT ;
    PORT
      LAYER M4 ;
      RECT 0.000 288.768 0.024 288.792 ;
    END
  END wd_in_A[25]
  PIN wd_in_B[25]
    DIRECTION INPUT ;
    USE SIGNAL ;
    SHAPE ABUTMENT ;
    PORT
      LAYER M4 ;
      RECT 51.656 288.768 51.680 288.792 ;
    END
  END wd_in_B[25]
  PIN wd_in_A[26]
    DIRECTION INPUT ;
    USE SIGNAL ;
    SHAPE ABUTMENT ;
    PORT
      LAYER M4 ;
      RECT 0.000 291.984 0.024 292.008 ;
    END
  END wd_in_A[26]
  PIN wd_in_B[26]
    DIRECTION INPUT ;
    USE SIGNAL ;
    SHAPE ABUTMENT ;
    PORT
      LAYER M4 ;
      RECT 51.656 291.984 51.680 292.008 ;
    END
  END wd_in_B[26]
  PIN wd_in_A[27]
    DIRECTION INPUT ;
    USE SIGNAL ;
    SHAPE ABUTMENT ;
    PORT
      LAYER M4 ;
      RECT 0.000 295.200 0.024 295.224 ;
    END
  END wd_in_A[27]
  PIN wd_in_B[27]
    DIRECTION INPUT ;
    USE SIGNAL ;
    SHAPE ABUTMENT ;
    PORT
      LAYER M4 ;
      RECT 51.656 295.200 51.680 295.224 ;
    END
  END wd_in_B[27]
  PIN wd_in_A[28]
    DIRECTION INPUT ;
    USE SIGNAL ;
    SHAPE ABUTMENT ;
    PORT
      LAYER M4 ;
      RECT 0.000 298.416 0.024 298.440 ;
    END
  END wd_in_A[28]
  PIN wd_in_B[28]
    DIRECTION INPUT ;
    USE SIGNAL ;
    SHAPE ABUTMENT ;
    PORT
      LAYER M4 ;
      RECT 51.656 298.416 51.680 298.440 ;
    END
  END wd_in_B[28]
  PIN wd_in_A[29]
    DIRECTION INPUT ;
    USE SIGNAL ;
    SHAPE ABUTMENT ;
    PORT
      LAYER M4 ;
      RECT 0.000 301.632 0.024 301.656 ;
    END
  END wd_in_A[29]
  PIN wd_in_B[29]
    DIRECTION INPUT ;
    USE SIGNAL ;
    SHAPE ABUTMENT ;
    PORT
      LAYER M4 ;
      RECT 51.656 301.632 51.680 301.656 ;
    END
  END wd_in_B[29]
  PIN wd_in_A[30]
    DIRECTION INPUT ;
    USE SIGNAL ;
    SHAPE ABUTMENT ;
    PORT
      LAYER M4 ;
      RECT 0.000 304.848 0.024 304.872 ;
    END
  END wd_in_A[30]
  PIN wd_in_B[30]
    DIRECTION INPUT ;
    USE SIGNAL ;
    SHAPE ABUTMENT ;
    PORT
      LAYER M4 ;
      RECT 51.656 304.848 51.680 304.872 ;
    END
  END wd_in_B[30]
  PIN wd_in_A[31]
    DIRECTION INPUT ;
    USE SIGNAL ;
    SHAPE ABUTMENT ;
    PORT
      LAYER M4 ;
      RECT 0.000 308.064 0.024 308.088 ;
    END
  END wd_in_A[31]
  PIN wd_in_B[31]
    DIRECTION INPUT ;
    USE SIGNAL ;
    SHAPE ABUTMENT ;
    PORT
      LAYER M4 ;
      RECT 51.656 308.064 51.680 308.088 ;
    END
  END wd_in_B[31]
  PIN addr_in_A[0]
    DIRECTION INPUT ;
    USE SIGNAL ;
    SHAPE ABUTMENT ;
    PORT
      LAYER M4 ;
      RECT 0.000 312.528 0.024 312.552 ;
    END
  END addr_in_A[0]
  PIN addr_in_B[0]
    DIRECTION INPUT ;
    USE SIGNAL ;
    SHAPE ABUTMENT ;
    PORT
      LAYER M4 ;
      RECT 51.656 312.528 51.680 312.552 ;
    END
  END addr_in_B[0]
  PIN addr_in_A[1]
    DIRECTION INPUT ;
    USE SIGNAL ;
    SHAPE ABUTMENT ;
    PORT
      LAYER M4 ;
      RECT 0.000 315.744 0.024 315.768 ;
    END
  END addr_in_A[1]
  PIN addr_in_B[1]
    DIRECTION INPUT ;
    USE SIGNAL ;
    SHAPE ABUTMENT ;
    PORT
      LAYER M4 ;
      RECT 51.656 315.744 51.680 315.768 ;
    END
  END addr_in_B[1]
  PIN addr_in_A[2]
    DIRECTION INPUT ;
    USE SIGNAL ;
    SHAPE ABUTMENT ;
    PORT
      LAYER M4 ;
      RECT 0.000 318.960 0.024 318.984 ;
    END
  END addr_in_A[2]
  PIN addr_in_B[2]
    DIRECTION INPUT ;
    USE SIGNAL ;
    SHAPE ABUTMENT ;
    PORT
      LAYER M4 ;
      RECT 51.656 318.960 51.680 318.984 ;
    END
  END addr_in_B[2]
  PIN addr_in_A[3]
    DIRECTION INPUT ;
    USE SIGNAL ;
    SHAPE ABUTMENT ;
    PORT
      LAYER M4 ;
      RECT 0.000 322.176 0.024 322.200 ;
    END
  END addr_in_A[3]
  PIN addr_in_B[3]
    DIRECTION INPUT ;
    USE SIGNAL ;
    SHAPE ABUTMENT ;
    PORT
      LAYER M4 ;
      RECT 51.656 322.176 51.680 322.200 ;
    END
  END addr_in_B[3]
  PIN addr_in_A[4]
    DIRECTION INPUT ;
    USE SIGNAL ;
    SHAPE ABUTMENT ;
    PORT
      LAYER M4 ;
      RECT 0.000 325.392 0.024 325.416 ;
    END
  END addr_in_A[4]
  PIN addr_in_B[4]
    DIRECTION INPUT ;
    USE SIGNAL ;
    SHAPE ABUTMENT ;
    PORT
      LAYER M4 ;
      RECT 51.656 325.392 51.680 325.416 ;
    END
  END addr_in_B[4]
  PIN addr_in_A[5]
    DIRECTION INPUT ;
    USE SIGNAL ;
    SHAPE ABUTMENT ;
    PORT
      LAYER M4 ;
      RECT 0.000 328.608 0.024 328.632 ;
    END
  END addr_in_A[5]
  PIN addr_in_B[5]
    DIRECTION INPUT ;
    USE SIGNAL ;
    SHAPE ABUTMENT ;
    PORT
      LAYER M4 ;
      RECT 51.656 328.608 51.680 328.632 ;
    END
  END addr_in_B[5]
  PIN addr_in_A[6]
    DIRECTION INPUT ;
    USE SIGNAL ;
    SHAPE ABUTMENT ;
    PORT
      LAYER M4 ;
      RECT 0.000 331.824 0.024 331.848 ;
    END
  END addr_in_A[6]
  PIN addr_in_B[6]
    DIRECTION INPUT ;
    USE SIGNAL ;
    SHAPE ABUTMENT ;
    PORT
      LAYER M4 ;
      RECT 51.656 331.824 51.680 331.848 ;
    END
  END addr_in_B[6]
  PIN addr_in_A[7]
    DIRECTION INPUT ;
    USE SIGNAL ;
    SHAPE ABUTMENT ;
    PORT
      LAYER M4 ;
      RECT 0.000 335.040 0.024 335.064 ;
    END
  END addr_in_A[7]
  PIN addr_in_B[7]
    DIRECTION INPUT ;
    USE SIGNAL ;
    SHAPE ABUTMENT ;
    PORT
      LAYER M4 ;
      RECT 51.656 335.040 51.680 335.064 ;
    END
  END addr_in_B[7]
  PIN addr_in_A[8]
    DIRECTION INPUT ;
    USE SIGNAL ;
    SHAPE ABUTMENT ;
    PORT
      LAYER M4 ;
      RECT 0.000 338.256 0.024 338.280 ;
    END
  END addr_in_A[8]
  PIN addr_in_B[8]
    DIRECTION INPUT ;
    USE SIGNAL ;
    SHAPE ABUTMENT ;
    PORT
      LAYER M4 ;
      RECT 51.656 338.256 51.680 338.280 ;
    END
  END addr_in_B[8]
  PIN addr_in_A[9]
    DIRECTION INPUT ;
    USE SIGNAL ;
    SHAPE ABUTMENT ;
    PORT
      LAYER M4 ;
      RECT 0.000 341.472 0.024 341.496 ;
    END
  END addr_in_A[9]
  PIN addr_in_B[9]
    DIRECTION INPUT ;
    USE SIGNAL ;
    SHAPE ABUTMENT ;
    PORT
      LAYER M4 ;
      RECT 51.656 341.472 51.680 341.496 ;
    END
  END addr_in_B[9]
  PIN addr_in_A[10]
    DIRECTION INPUT ;
    USE SIGNAL ;
    SHAPE ABUTMENT ;
    PORT
      LAYER M4 ;
      RECT 0.000 344.688 0.024 344.712 ;
    END
  END addr_in_A[10]
  PIN addr_in_B[10]
    DIRECTION INPUT ;
    USE SIGNAL ;
    SHAPE ABUTMENT ;
    PORT
      LAYER M4 ;
      RECT 51.656 344.688 51.680 344.712 ;
    END
  END addr_in_B[10]
  PIN addr_in_A[11]
    DIRECTION INPUT ;
    USE SIGNAL ;
    SHAPE ABUTMENT ;
    PORT
      LAYER M4 ;
      RECT 0.000 347.904 0.024 347.928 ;
    END
  END addr_in_A[11]
  PIN addr_in_B[11]
    DIRECTION INPUT ;
    USE SIGNAL ;
    SHAPE ABUTMENT ;
    PORT
      LAYER M4 ;
      RECT 51.656 347.904 51.680 347.928 ;
    END
  END addr_in_B[11]
  PIN addr_in_A[12]
    DIRECTION INPUT ;
    USE SIGNAL ;
    SHAPE ABUTMENT ;
    PORT
      LAYER M4 ;
      RECT 0.000 351.120 0.024 351.144 ;
    END
  END addr_in_A[12]
  PIN addr_in_B[12]
    DIRECTION INPUT ;
    USE SIGNAL ;
    SHAPE ABUTMENT ;
    PORT
      LAYER M4 ;
      RECT 51.656 351.120 51.680 351.144 ;
    END
  END addr_in_B[12]
  PIN we_in_A
    DIRECTION INPUT ;
    USE SIGNAL ;
    SHAPE ABUTMENT ;
    PORT
      LAYER M4 ;
      RECT 0.000 355.584 0.024 355.608 ;
    END
  END we_in_A
  PIN we_in_B
    DIRECTION INPUT ;
    USE SIGNAL ;
    SHAPE ABUTMENT ;
    PORT
      LAYER M4 ;
      RECT 51.656 355.584 51.680 355.608 ;
    END
  END we_in_B
  PIN ce_in_A
    DIRECTION INPUT ;
    USE SIGNAL ;
    SHAPE ABUTMENT ;
    PORT
      LAYER M4 ;
      RECT 0.000 358.800 0.024 358.824 ;
    END
  END ce_in_A
  PIN clk_A
    DIRECTION INPUT ;
    USE SIGNAL ;
    SHAPE ABUTMENT ;
    PORT
      LAYER M4 ;
      RECT 0.000 362.016 0.024 362.040 ;
    END
  END clk_A
  PIN ce_in_B
    DIRECTION INPUT ;
    USE SIGNAL ;
    SHAPE ABUTMENT ;
    PORT
      LAYER M4 ;
      RECT 0.000 365.232 0.024 365.256 ;
    END
  END ce_in_B
  PIN clk_B
    DIRECTION INPUT ;
    USE SIGNAL ;
    SHAPE ABUTMENT ;
    PORT
      LAYER M4 ;
      RECT 0.000 368.448 0.024 368.472 ;
    END
  END clk_B
  PIN VSS
    DIRECTION INOUT ;
    USE GROUND ;
    PORT
      LAYER M4 ;
      RECT 0.048 0.000 51.632 0.096 ;
      RECT 0.048 0.768 51.632 0.864 ;
      RECT 0.048 1.536 51.632 1.632 ;
      RECT 0.048 2.304 51.632 2.400 ;
      RECT 0.048 3.072 51.632 3.168 ;
      RECT 0.048 3.840 51.632 3.936 ;
      RECT 0.048 4.608 51.632 4.704 ;
      RECT 0.048 5.376 51.632 5.472 ;
      RECT 0.048 6.144 51.632 6.240 ;
      RECT 0.048 6.912 51.632 7.008 ;
      RECT 0.048 7.680 51.632 7.776 ;
      RECT 0.048 8.448 51.632 8.544 ;
      RECT 0.048 9.216 51.632 9.312 ;
      RECT 0.048 9.984 51.632 10.080 ;
      RECT 0.048 10.752 51.632 10.848 ;
      RECT 0.048 11.520 51.632 11.616 ;
      RECT 0.048 12.288 51.632 12.384 ;
      RECT 0.048 13.056 51.632 13.152 ;
      RECT 0.048 13.824 51.632 13.920 ;
      RECT 0.048 14.592 51.632 14.688 ;
      RECT 0.048 15.360 51.632 15.456 ;
      RECT 0.048 16.128 51.632 16.224 ;
      RECT 0.048 16.896 51.632 16.992 ;
      RECT 0.048 17.664 51.632 17.760 ;
      RECT 0.048 18.432 51.632 18.528 ;
      RECT 0.048 19.200 51.632 19.296 ;
      RECT 0.048 19.968 51.632 20.064 ;
      RECT 0.048 20.736 51.632 20.832 ;
      RECT 0.048 21.504 51.632 21.600 ;
      RECT 0.048 22.272 51.632 22.368 ;
      RECT 0.048 23.040 51.632 23.136 ;
      RECT 0.048 23.808 51.632 23.904 ;
      RECT 0.048 24.576 51.632 24.672 ;
      RECT 0.048 25.344 51.632 25.440 ;
      RECT 0.048 26.112 51.632 26.208 ;
      RECT 0.048 26.880 51.632 26.976 ;
      RECT 0.048 27.648 51.632 27.744 ;
      RECT 0.048 28.416 51.632 28.512 ;
      RECT 0.048 29.184 51.632 29.280 ;
      RECT 0.048 29.952 51.632 30.048 ;
      RECT 0.048 30.720 51.632 30.816 ;
      RECT 0.048 31.488 51.632 31.584 ;
      RECT 0.048 32.256 51.632 32.352 ;
      RECT 0.048 33.024 51.632 33.120 ;
      RECT 0.048 33.792 51.632 33.888 ;
      RECT 0.048 34.560 51.632 34.656 ;
      RECT 0.048 35.328 51.632 35.424 ;
      RECT 0.048 36.096 51.632 36.192 ;
      RECT 0.048 36.864 51.632 36.960 ;
      RECT 0.048 37.632 51.632 37.728 ;
      RECT 0.048 38.400 51.632 38.496 ;
      RECT 0.048 39.168 51.632 39.264 ;
      RECT 0.048 39.936 51.632 40.032 ;
      RECT 0.048 40.704 51.632 40.800 ;
      RECT 0.048 41.472 51.632 41.568 ;
      RECT 0.048 42.240 51.632 42.336 ;
      RECT 0.048 43.008 51.632 43.104 ;
      RECT 0.048 43.776 51.632 43.872 ;
      RECT 0.048 44.544 51.632 44.640 ;
      RECT 0.048 45.312 51.632 45.408 ;
      RECT 0.048 46.080 51.632 46.176 ;
      RECT 0.048 46.848 51.632 46.944 ;
      RECT 0.048 47.616 51.632 47.712 ;
      RECT 0.048 48.384 51.632 48.480 ;
      RECT 0.048 49.152 51.632 49.248 ;
      RECT 0.048 49.920 51.632 50.016 ;
      RECT 0.048 50.688 51.632 50.784 ;
      RECT 0.048 51.456 51.632 51.552 ;
      RECT 0.048 52.224 51.632 52.320 ;
      RECT 0.048 52.992 51.632 53.088 ;
      RECT 0.048 53.760 51.632 53.856 ;
      RECT 0.048 54.528 51.632 54.624 ;
      RECT 0.048 55.296 51.632 55.392 ;
      RECT 0.048 56.064 51.632 56.160 ;
      RECT 0.048 56.832 51.632 56.928 ;
      RECT 0.048 57.600 51.632 57.696 ;
      RECT 0.048 58.368 51.632 58.464 ;
      RECT 0.048 59.136 51.632 59.232 ;
      RECT 0.048 59.904 51.632 60.000 ;
      RECT 0.048 60.672 51.632 60.768 ;
      RECT 0.048 61.440 51.632 61.536 ;
      RECT 0.048 62.208 51.632 62.304 ;
      RECT 0.048 62.976 51.632 63.072 ;
      RECT 0.048 63.744 51.632 63.840 ;
      RECT 0.048 64.512 51.632 64.608 ;
      RECT 0.048 65.280 51.632 65.376 ;
      RECT 0.048 66.048 51.632 66.144 ;
      RECT 0.048 66.816 51.632 66.912 ;
      RECT 0.048 67.584 51.632 67.680 ;
      RECT 0.048 68.352 51.632 68.448 ;
      RECT 0.048 69.120 51.632 69.216 ;
      RECT 0.048 69.888 51.632 69.984 ;
      RECT 0.048 70.656 51.632 70.752 ;
      RECT 0.048 71.424 51.632 71.520 ;
      RECT 0.048 72.192 51.632 72.288 ;
      RECT 0.048 72.960 51.632 73.056 ;
      RECT 0.048 73.728 51.632 73.824 ;
      RECT 0.048 74.496 51.632 74.592 ;
      RECT 0.048 75.264 51.632 75.360 ;
      RECT 0.048 76.032 51.632 76.128 ;
      RECT 0.048 76.800 51.632 76.896 ;
      RECT 0.048 77.568 51.632 77.664 ;
      RECT 0.048 78.336 51.632 78.432 ;
      RECT 0.048 79.104 51.632 79.200 ;
      RECT 0.048 79.872 51.632 79.968 ;
      RECT 0.048 80.640 51.632 80.736 ;
      RECT 0.048 81.408 51.632 81.504 ;
      RECT 0.048 82.176 51.632 82.272 ;
      RECT 0.048 82.944 51.632 83.040 ;
      RECT 0.048 83.712 51.632 83.808 ;
      RECT 0.048 84.480 51.632 84.576 ;
      RECT 0.048 85.248 51.632 85.344 ;
      RECT 0.048 86.016 51.632 86.112 ;
      RECT 0.048 86.784 51.632 86.880 ;
      RECT 0.048 87.552 51.632 87.648 ;
      RECT 0.048 88.320 51.632 88.416 ;
      RECT 0.048 89.088 51.632 89.184 ;
      RECT 0.048 89.856 51.632 89.952 ;
      RECT 0.048 90.624 51.632 90.720 ;
      RECT 0.048 91.392 51.632 91.488 ;
      RECT 0.048 92.160 51.632 92.256 ;
      RECT 0.048 92.928 51.632 93.024 ;
      RECT 0.048 93.696 51.632 93.792 ;
      RECT 0.048 94.464 51.632 94.560 ;
      RECT 0.048 95.232 51.632 95.328 ;
      RECT 0.048 96.000 51.632 96.096 ;
      RECT 0.048 96.768 51.632 96.864 ;
      RECT 0.048 97.536 51.632 97.632 ;
      RECT 0.048 98.304 51.632 98.400 ;
      RECT 0.048 99.072 51.632 99.168 ;
      RECT 0.048 99.840 51.632 99.936 ;
      RECT 0.048 100.608 51.632 100.704 ;
      RECT 0.048 101.376 51.632 101.472 ;
      RECT 0.048 102.144 51.632 102.240 ;
      RECT 0.048 102.912 51.632 103.008 ;
      RECT 0.048 103.680 51.632 103.776 ;
      RECT 0.048 104.448 51.632 104.544 ;
      RECT 0.048 105.216 51.632 105.312 ;
      RECT 0.048 105.984 51.632 106.080 ;
      RECT 0.048 106.752 51.632 106.848 ;
      RECT 0.048 107.520 51.632 107.616 ;
      RECT 0.048 108.288 51.632 108.384 ;
      RECT 0.048 109.056 51.632 109.152 ;
      RECT 0.048 109.824 51.632 109.920 ;
      RECT 0.048 110.592 51.632 110.688 ;
      RECT 0.048 111.360 51.632 111.456 ;
      RECT 0.048 112.128 51.632 112.224 ;
      RECT 0.048 112.896 51.632 112.992 ;
      RECT 0.048 113.664 51.632 113.760 ;
      RECT 0.048 114.432 51.632 114.528 ;
      RECT 0.048 115.200 51.632 115.296 ;
      RECT 0.048 115.968 51.632 116.064 ;
      RECT 0.048 116.736 51.632 116.832 ;
      RECT 0.048 117.504 51.632 117.600 ;
      RECT 0.048 118.272 51.632 118.368 ;
      RECT 0.048 119.040 51.632 119.136 ;
      RECT 0.048 119.808 51.632 119.904 ;
      RECT 0.048 120.576 51.632 120.672 ;
      RECT 0.048 121.344 51.632 121.440 ;
      RECT 0.048 122.112 51.632 122.208 ;
      RECT 0.048 122.880 51.632 122.976 ;
      RECT 0.048 123.648 51.632 123.744 ;
      RECT 0.048 124.416 51.632 124.512 ;
      RECT 0.048 125.184 51.632 125.280 ;
      RECT 0.048 125.952 51.632 126.048 ;
      RECT 0.048 126.720 51.632 126.816 ;
      RECT 0.048 127.488 51.632 127.584 ;
      RECT 0.048 128.256 51.632 128.352 ;
      RECT 0.048 129.024 51.632 129.120 ;
      RECT 0.048 129.792 51.632 129.888 ;
      RECT 0.048 130.560 51.632 130.656 ;
      RECT 0.048 131.328 51.632 131.424 ;
      RECT 0.048 132.096 51.632 132.192 ;
      RECT 0.048 132.864 51.632 132.960 ;
      RECT 0.048 133.632 51.632 133.728 ;
      RECT 0.048 134.400 51.632 134.496 ;
      RECT 0.048 135.168 51.632 135.264 ;
      RECT 0.048 135.936 51.632 136.032 ;
      RECT 0.048 136.704 51.632 136.800 ;
      RECT 0.048 137.472 51.632 137.568 ;
      RECT 0.048 138.240 51.632 138.336 ;
      RECT 0.048 139.008 51.632 139.104 ;
      RECT 0.048 139.776 51.632 139.872 ;
      RECT 0.048 140.544 51.632 140.640 ;
      RECT 0.048 141.312 51.632 141.408 ;
      RECT 0.048 142.080 51.632 142.176 ;
      RECT 0.048 142.848 51.632 142.944 ;
      RECT 0.048 143.616 51.632 143.712 ;
      RECT 0.048 144.384 51.632 144.480 ;
      RECT 0.048 145.152 51.632 145.248 ;
      RECT 0.048 145.920 51.632 146.016 ;
      RECT 0.048 146.688 51.632 146.784 ;
      RECT 0.048 147.456 51.632 147.552 ;
      RECT 0.048 148.224 51.632 148.320 ;
      RECT 0.048 148.992 51.632 149.088 ;
      RECT 0.048 149.760 51.632 149.856 ;
      RECT 0.048 150.528 51.632 150.624 ;
      RECT 0.048 151.296 51.632 151.392 ;
      RECT 0.048 152.064 51.632 152.160 ;
      RECT 0.048 152.832 51.632 152.928 ;
      RECT 0.048 153.600 51.632 153.696 ;
      RECT 0.048 154.368 51.632 154.464 ;
      RECT 0.048 155.136 51.632 155.232 ;
      RECT 0.048 155.904 51.632 156.000 ;
      RECT 0.048 156.672 51.632 156.768 ;
      RECT 0.048 157.440 51.632 157.536 ;
      RECT 0.048 158.208 51.632 158.304 ;
      RECT 0.048 158.976 51.632 159.072 ;
      RECT 0.048 159.744 51.632 159.840 ;
      RECT 0.048 160.512 51.632 160.608 ;
      RECT 0.048 161.280 51.632 161.376 ;
      RECT 0.048 162.048 51.632 162.144 ;
      RECT 0.048 162.816 51.632 162.912 ;
      RECT 0.048 163.584 51.632 163.680 ;
      RECT 0.048 164.352 51.632 164.448 ;
      RECT 0.048 165.120 51.632 165.216 ;
      RECT 0.048 165.888 51.632 165.984 ;
      RECT 0.048 166.656 51.632 166.752 ;
      RECT 0.048 167.424 51.632 167.520 ;
      RECT 0.048 168.192 51.632 168.288 ;
      RECT 0.048 168.960 51.632 169.056 ;
      RECT 0.048 169.728 51.632 169.824 ;
      RECT 0.048 170.496 51.632 170.592 ;
      RECT 0.048 171.264 51.632 171.360 ;
      RECT 0.048 172.032 51.632 172.128 ;
      RECT 0.048 172.800 51.632 172.896 ;
      RECT 0.048 173.568 51.632 173.664 ;
      RECT 0.048 174.336 51.632 174.432 ;
      RECT 0.048 175.104 51.632 175.200 ;
      RECT 0.048 175.872 51.632 175.968 ;
      RECT 0.048 176.640 51.632 176.736 ;
      RECT 0.048 177.408 51.632 177.504 ;
      RECT 0.048 178.176 51.632 178.272 ;
      RECT 0.048 178.944 51.632 179.040 ;
      RECT 0.048 179.712 51.632 179.808 ;
      RECT 0.048 180.480 51.632 180.576 ;
      RECT 0.048 181.248 51.632 181.344 ;
      RECT 0.048 182.016 51.632 182.112 ;
      RECT 0.048 182.784 51.632 182.880 ;
      RECT 0.048 183.552 51.632 183.648 ;
      RECT 0.048 184.320 51.632 184.416 ;
      RECT 0.048 185.088 51.632 185.184 ;
      RECT 0.048 185.856 51.632 185.952 ;
      RECT 0.048 186.624 51.632 186.720 ;
      RECT 0.048 187.392 51.632 187.488 ;
      RECT 0.048 188.160 51.632 188.256 ;
      RECT 0.048 188.928 51.632 189.024 ;
      RECT 0.048 189.696 51.632 189.792 ;
      RECT 0.048 190.464 51.632 190.560 ;
      RECT 0.048 191.232 51.632 191.328 ;
      RECT 0.048 192.000 51.632 192.096 ;
      RECT 0.048 192.768 51.632 192.864 ;
      RECT 0.048 193.536 51.632 193.632 ;
      RECT 0.048 194.304 51.632 194.400 ;
      RECT 0.048 195.072 51.632 195.168 ;
      RECT 0.048 195.840 51.632 195.936 ;
      RECT 0.048 196.608 51.632 196.704 ;
      RECT 0.048 197.376 51.632 197.472 ;
      RECT 0.048 198.144 51.632 198.240 ;
      RECT 0.048 198.912 51.632 199.008 ;
      RECT 0.048 199.680 51.632 199.776 ;
      RECT 0.048 200.448 51.632 200.544 ;
      RECT 0.048 201.216 51.632 201.312 ;
      RECT 0.048 201.984 51.632 202.080 ;
      RECT 0.048 202.752 51.632 202.848 ;
      RECT 0.048 203.520 51.632 203.616 ;
      RECT 0.048 204.288 51.632 204.384 ;
      RECT 0.048 205.056 51.632 205.152 ;
      RECT 0.048 205.824 51.632 205.920 ;
      RECT 0.048 206.592 51.632 206.688 ;
      RECT 0.048 207.360 51.632 207.456 ;
      RECT 0.048 208.128 51.632 208.224 ;
      RECT 0.048 208.896 51.632 208.992 ;
      RECT 0.048 209.664 51.632 209.760 ;
      RECT 0.048 210.432 51.632 210.528 ;
      RECT 0.048 211.200 51.632 211.296 ;
      RECT 0.048 211.968 51.632 212.064 ;
      RECT 0.048 212.736 51.632 212.832 ;
      RECT 0.048 213.504 51.632 213.600 ;
      RECT 0.048 214.272 51.632 214.368 ;
      RECT 0.048 215.040 51.632 215.136 ;
      RECT 0.048 215.808 51.632 215.904 ;
      RECT 0.048 216.576 51.632 216.672 ;
      RECT 0.048 217.344 51.632 217.440 ;
      RECT 0.048 218.112 51.632 218.208 ;
      RECT 0.048 218.880 51.632 218.976 ;
      RECT 0.048 219.648 51.632 219.744 ;
      RECT 0.048 220.416 51.632 220.512 ;
      RECT 0.048 221.184 51.632 221.280 ;
      RECT 0.048 221.952 51.632 222.048 ;
      RECT 0.048 222.720 51.632 222.816 ;
      RECT 0.048 223.488 51.632 223.584 ;
      RECT 0.048 224.256 51.632 224.352 ;
      RECT 0.048 225.024 51.632 225.120 ;
      RECT 0.048 225.792 51.632 225.888 ;
      RECT 0.048 226.560 51.632 226.656 ;
      RECT 0.048 227.328 51.632 227.424 ;
      RECT 0.048 228.096 51.632 228.192 ;
      RECT 0.048 228.864 51.632 228.960 ;
      RECT 0.048 229.632 51.632 229.728 ;
      RECT 0.048 230.400 51.632 230.496 ;
      RECT 0.048 231.168 51.632 231.264 ;
      RECT 0.048 231.936 51.632 232.032 ;
      RECT 0.048 232.704 51.632 232.800 ;
      RECT 0.048 233.472 51.632 233.568 ;
      RECT 0.048 234.240 51.632 234.336 ;
      RECT 0.048 235.008 51.632 235.104 ;
      RECT 0.048 235.776 51.632 235.872 ;
      RECT 0.048 236.544 51.632 236.640 ;
      RECT 0.048 237.312 51.632 237.408 ;
      RECT 0.048 238.080 51.632 238.176 ;
      RECT 0.048 238.848 51.632 238.944 ;
      RECT 0.048 239.616 51.632 239.712 ;
      RECT 0.048 240.384 51.632 240.480 ;
      RECT 0.048 241.152 51.632 241.248 ;
      RECT 0.048 241.920 51.632 242.016 ;
      RECT 0.048 242.688 51.632 242.784 ;
      RECT 0.048 243.456 51.632 243.552 ;
      RECT 0.048 244.224 51.632 244.320 ;
      RECT 0.048 244.992 51.632 245.088 ;
      RECT 0.048 245.760 51.632 245.856 ;
      RECT 0.048 246.528 51.632 246.624 ;
      RECT 0.048 247.296 51.632 247.392 ;
      RECT 0.048 248.064 51.632 248.160 ;
      RECT 0.048 248.832 51.632 248.928 ;
      RECT 0.048 249.600 51.632 249.696 ;
      RECT 0.048 250.368 51.632 250.464 ;
      RECT 0.048 251.136 51.632 251.232 ;
      RECT 0.048 251.904 51.632 252.000 ;
      RECT 0.048 252.672 51.632 252.768 ;
      RECT 0.048 253.440 51.632 253.536 ;
      RECT 0.048 254.208 51.632 254.304 ;
      RECT 0.048 254.976 51.632 255.072 ;
      RECT 0.048 255.744 51.632 255.840 ;
      RECT 0.048 256.512 51.632 256.608 ;
      RECT 0.048 257.280 51.632 257.376 ;
      RECT 0.048 258.048 51.632 258.144 ;
      RECT 0.048 258.816 51.632 258.912 ;
      RECT 0.048 259.584 51.632 259.680 ;
      RECT 0.048 260.352 51.632 260.448 ;
      RECT 0.048 261.120 51.632 261.216 ;
      RECT 0.048 261.888 51.632 261.984 ;
      RECT 0.048 262.656 51.632 262.752 ;
      RECT 0.048 263.424 51.632 263.520 ;
      RECT 0.048 264.192 51.632 264.288 ;
      RECT 0.048 264.960 51.632 265.056 ;
      RECT 0.048 265.728 51.632 265.824 ;
      RECT 0.048 266.496 51.632 266.592 ;
      RECT 0.048 267.264 51.632 267.360 ;
      RECT 0.048 268.032 51.632 268.128 ;
      RECT 0.048 268.800 51.632 268.896 ;
      RECT 0.048 269.568 51.632 269.664 ;
      RECT 0.048 270.336 51.632 270.432 ;
      RECT 0.048 271.104 51.632 271.200 ;
      RECT 0.048 271.872 51.632 271.968 ;
      RECT 0.048 272.640 51.632 272.736 ;
      RECT 0.048 273.408 51.632 273.504 ;
      RECT 0.048 274.176 51.632 274.272 ;
      RECT 0.048 274.944 51.632 275.040 ;
      RECT 0.048 275.712 51.632 275.808 ;
      RECT 0.048 276.480 51.632 276.576 ;
      RECT 0.048 277.248 51.632 277.344 ;
      RECT 0.048 278.016 51.632 278.112 ;
      RECT 0.048 278.784 51.632 278.880 ;
      RECT 0.048 279.552 51.632 279.648 ;
      RECT 0.048 280.320 51.632 280.416 ;
      RECT 0.048 281.088 51.632 281.184 ;
      RECT 0.048 281.856 51.632 281.952 ;
      RECT 0.048 282.624 51.632 282.720 ;
      RECT 0.048 283.392 51.632 283.488 ;
      RECT 0.048 284.160 51.632 284.256 ;
      RECT 0.048 284.928 51.632 285.024 ;
      RECT 0.048 285.696 51.632 285.792 ;
      RECT 0.048 286.464 51.632 286.560 ;
      RECT 0.048 287.232 51.632 287.328 ;
      RECT 0.048 288.000 51.632 288.096 ;
      RECT 0.048 288.768 51.632 288.864 ;
      RECT 0.048 289.536 51.632 289.632 ;
      RECT 0.048 290.304 51.632 290.400 ;
      RECT 0.048 291.072 51.632 291.168 ;
      RECT 0.048 291.840 51.632 291.936 ;
      RECT 0.048 292.608 51.632 292.704 ;
      RECT 0.048 293.376 51.632 293.472 ;
      RECT 0.048 294.144 51.632 294.240 ;
      RECT 0.048 294.912 51.632 295.008 ;
      RECT 0.048 295.680 51.632 295.776 ;
      RECT 0.048 296.448 51.632 296.544 ;
      RECT 0.048 297.216 51.632 297.312 ;
      RECT 0.048 297.984 51.632 298.080 ;
      RECT 0.048 298.752 51.632 298.848 ;
      RECT 0.048 299.520 51.632 299.616 ;
      RECT 0.048 300.288 51.632 300.384 ;
      RECT 0.048 301.056 51.632 301.152 ;
      RECT 0.048 301.824 51.632 301.920 ;
      RECT 0.048 302.592 51.632 302.688 ;
      RECT 0.048 303.360 51.632 303.456 ;
      RECT 0.048 304.128 51.632 304.224 ;
      RECT 0.048 304.896 51.632 304.992 ;
      RECT 0.048 305.664 51.632 305.760 ;
      RECT 0.048 306.432 51.632 306.528 ;
      RECT 0.048 307.200 51.632 307.296 ;
      RECT 0.048 307.968 51.632 308.064 ;
      RECT 0.048 308.736 51.632 308.832 ;
      RECT 0.048 309.504 51.632 309.600 ;
      RECT 0.048 310.272 51.632 310.368 ;
      RECT 0.048 311.040 51.632 311.136 ;
      RECT 0.048 311.808 51.632 311.904 ;
      RECT 0.048 312.576 51.632 312.672 ;
      RECT 0.048 313.344 51.632 313.440 ;
      RECT 0.048 314.112 51.632 314.208 ;
      RECT 0.048 314.880 51.632 314.976 ;
      RECT 0.048 315.648 51.632 315.744 ;
      RECT 0.048 316.416 51.632 316.512 ;
      RECT 0.048 317.184 51.632 317.280 ;
      RECT 0.048 317.952 51.632 318.048 ;
      RECT 0.048 318.720 51.632 318.816 ;
      RECT 0.048 319.488 51.632 319.584 ;
      RECT 0.048 320.256 51.632 320.352 ;
      RECT 0.048 321.024 51.632 321.120 ;
      RECT 0.048 321.792 51.632 321.888 ;
      RECT 0.048 322.560 51.632 322.656 ;
      RECT 0.048 323.328 51.632 323.424 ;
      RECT 0.048 324.096 51.632 324.192 ;
      RECT 0.048 324.864 51.632 324.960 ;
      RECT 0.048 325.632 51.632 325.728 ;
      RECT 0.048 326.400 51.632 326.496 ;
      RECT 0.048 327.168 51.632 327.264 ;
      RECT 0.048 327.936 51.632 328.032 ;
      RECT 0.048 328.704 51.632 328.800 ;
      RECT 0.048 329.472 51.632 329.568 ;
      RECT 0.048 330.240 51.632 330.336 ;
      RECT 0.048 331.008 51.632 331.104 ;
      RECT 0.048 331.776 51.632 331.872 ;
      RECT 0.048 332.544 51.632 332.640 ;
      RECT 0.048 333.312 51.632 333.408 ;
      RECT 0.048 334.080 51.632 334.176 ;
      RECT 0.048 334.848 51.632 334.944 ;
      RECT 0.048 335.616 51.632 335.712 ;
      RECT 0.048 336.384 51.632 336.480 ;
      RECT 0.048 337.152 51.632 337.248 ;
      RECT 0.048 337.920 51.632 338.016 ;
      RECT 0.048 338.688 51.632 338.784 ;
      RECT 0.048 339.456 51.632 339.552 ;
      RECT 0.048 340.224 51.632 340.320 ;
      RECT 0.048 340.992 51.632 341.088 ;
      RECT 0.048 341.760 51.632 341.856 ;
      RECT 0.048 342.528 51.632 342.624 ;
      RECT 0.048 343.296 51.632 343.392 ;
      RECT 0.048 344.064 51.632 344.160 ;
      RECT 0.048 344.832 51.632 344.928 ;
      RECT 0.048 345.600 51.632 345.696 ;
      RECT 0.048 346.368 51.632 346.464 ;
      RECT 0.048 347.136 51.632 347.232 ;
      RECT 0.048 347.904 51.632 348.000 ;
      RECT 0.048 348.672 51.632 348.768 ;
      RECT 0.048 349.440 51.632 349.536 ;
      RECT 0.048 350.208 51.632 350.304 ;
      RECT 0.048 350.976 51.632 351.072 ;
      RECT 0.048 351.744 51.632 351.840 ;
      RECT 0.048 352.512 51.632 352.608 ;
      RECT 0.048 353.280 51.632 353.376 ;
      RECT 0.048 354.048 51.632 354.144 ;
      RECT 0.048 354.816 51.632 354.912 ;
      RECT 0.048 355.584 51.632 355.680 ;
      RECT 0.048 356.352 51.632 356.448 ;
      RECT 0.048 357.120 51.632 357.216 ;
      RECT 0.048 357.888 51.632 357.984 ;
      RECT 0.048 358.656 51.632 358.752 ;
      RECT 0.048 359.424 51.632 359.520 ;
      RECT 0.048 360.192 51.632 360.288 ;
      RECT 0.048 360.960 51.632 361.056 ;
      RECT 0.048 361.728 51.632 361.824 ;
      RECT 0.048 362.496 51.632 362.592 ;
      RECT 0.048 363.264 51.632 363.360 ;
      RECT 0.048 364.032 51.632 364.128 ;
      RECT 0.048 364.800 51.632 364.896 ;
    END
  END VSS
  PIN VDD
    DIRECTION INOUT ;
    USE POWER ;
    PORT
      LAYER M4 ;
      RECT 0.048 0.384 51.632 0.480 ;
      RECT 0.048 1.152 51.632 1.248 ;
      RECT 0.048 1.920 51.632 2.016 ;
      RECT 0.048 2.688 51.632 2.784 ;
      RECT 0.048 3.456 51.632 3.552 ;
      RECT 0.048 4.224 51.632 4.320 ;
      RECT 0.048 4.992 51.632 5.088 ;
      RECT 0.048 5.760 51.632 5.856 ;
      RECT 0.048 6.528 51.632 6.624 ;
      RECT 0.048 7.296 51.632 7.392 ;
      RECT 0.048 8.064 51.632 8.160 ;
      RECT 0.048 8.832 51.632 8.928 ;
      RECT 0.048 9.600 51.632 9.696 ;
      RECT 0.048 10.368 51.632 10.464 ;
      RECT 0.048 11.136 51.632 11.232 ;
      RECT 0.048 11.904 51.632 12.000 ;
      RECT 0.048 12.672 51.632 12.768 ;
      RECT 0.048 13.440 51.632 13.536 ;
      RECT 0.048 14.208 51.632 14.304 ;
      RECT 0.048 14.976 51.632 15.072 ;
      RECT 0.048 15.744 51.632 15.840 ;
      RECT 0.048 16.512 51.632 16.608 ;
      RECT 0.048 17.280 51.632 17.376 ;
      RECT 0.048 18.048 51.632 18.144 ;
      RECT 0.048 18.816 51.632 18.912 ;
      RECT 0.048 19.584 51.632 19.680 ;
      RECT 0.048 20.352 51.632 20.448 ;
      RECT 0.048 21.120 51.632 21.216 ;
      RECT 0.048 21.888 51.632 21.984 ;
      RECT 0.048 22.656 51.632 22.752 ;
      RECT 0.048 23.424 51.632 23.520 ;
      RECT 0.048 24.192 51.632 24.288 ;
      RECT 0.048 24.960 51.632 25.056 ;
      RECT 0.048 25.728 51.632 25.824 ;
      RECT 0.048 26.496 51.632 26.592 ;
      RECT 0.048 27.264 51.632 27.360 ;
      RECT 0.048 28.032 51.632 28.128 ;
      RECT 0.048 28.800 51.632 28.896 ;
      RECT 0.048 29.568 51.632 29.664 ;
      RECT 0.048 30.336 51.632 30.432 ;
      RECT 0.048 31.104 51.632 31.200 ;
      RECT 0.048 31.872 51.632 31.968 ;
      RECT 0.048 32.640 51.632 32.736 ;
      RECT 0.048 33.408 51.632 33.504 ;
      RECT 0.048 34.176 51.632 34.272 ;
      RECT 0.048 34.944 51.632 35.040 ;
      RECT 0.048 35.712 51.632 35.808 ;
      RECT 0.048 36.480 51.632 36.576 ;
      RECT 0.048 37.248 51.632 37.344 ;
      RECT 0.048 38.016 51.632 38.112 ;
      RECT 0.048 38.784 51.632 38.880 ;
      RECT 0.048 39.552 51.632 39.648 ;
      RECT 0.048 40.320 51.632 40.416 ;
      RECT 0.048 41.088 51.632 41.184 ;
      RECT 0.048 41.856 51.632 41.952 ;
      RECT 0.048 42.624 51.632 42.720 ;
      RECT 0.048 43.392 51.632 43.488 ;
      RECT 0.048 44.160 51.632 44.256 ;
      RECT 0.048 44.928 51.632 45.024 ;
      RECT 0.048 45.696 51.632 45.792 ;
      RECT 0.048 46.464 51.632 46.560 ;
      RECT 0.048 47.232 51.632 47.328 ;
      RECT 0.048 48.000 51.632 48.096 ;
      RECT 0.048 48.768 51.632 48.864 ;
      RECT 0.048 49.536 51.632 49.632 ;
      RECT 0.048 50.304 51.632 50.400 ;
      RECT 0.048 51.072 51.632 51.168 ;
      RECT 0.048 51.840 51.632 51.936 ;
      RECT 0.048 52.608 51.632 52.704 ;
      RECT 0.048 53.376 51.632 53.472 ;
      RECT 0.048 54.144 51.632 54.240 ;
      RECT 0.048 54.912 51.632 55.008 ;
      RECT 0.048 55.680 51.632 55.776 ;
      RECT 0.048 56.448 51.632 56.544 ;
      RECT 0.048 57.216 51.632 57.312 ;
      RECT 0.048 57.984 51.632 58.080 ;
      RECT 0.048 58.752 51.632 58.848 ;
      RECT 0.048 59.520 51.632 59.616 ;
      RECT 0.048 60.288 51.632 60.384 ;
      RECT 0.048 61.056 51.632 61.152 ;
      RECT 0.048 61.824 51.632 61.920 ;
      RECT 0.048 62.592 51.632 62.688 ;
      RECT 0.048 63.360 51.632 63.456 ;
      RECT 0.048 64.128 51.632 64.224 ;
      RECT 0.048 64.896 51.632 64.992 ;
      RECT 0.048 65.664 51.632 65.760 ;
      RECT 0.048 66.432 51.632 66.528 ;
      RECT 0.048 67.200 51.632 67.296 ;
      RECT 0.048 67.968 51.632 68.064 ;
      RECT 0.048 68.736 51.632 68.832 ;
      RECT 0.048 69.504 51.632 69.600 ;
      RECT 0.048 70.272 51.632 70.368 ;
      RECT 0.048 71.040 51.632 71.136 ;
      RECT 0.048 71.808 51.632 71.904 ;
      RECT 0.048 72.576 51.632 72.672 ;
      RECT 0.048 73.344 51.632 73.440 ;
      RECT 0.048 74.112 51.632 74.208 ;
      RECT 0.048 74.880 51.632 74.976 ;
      RECT 0.048 75.648 51.632 75.744 ;
      RECT 0.048 76.416 51.632 76.512 ;
      RECT 0.048 77.184 51.632 77.280 ;
      RECT 0.048 77.952 51.632 78.048 ;
      RECT 0.048 78.720 51.632 78.816 ;
      RECT 0.048 79.488 51.632 79.584 ;
      RECT 0.048 80.256 51.632 80.352 ;
      RECT 0.048 81.024 51.632 81.120 ;
      RECT 0.048 81.792 51.632 81.888 ;
      RECT 0.048 82.560 51.632 82.656 ;
      RECT 0.048 83.328 51.632 83.424 ;
      RECT 0.048 84.096 51.632 84.192 ;
      RECT 0.048 84.864 51.632 84.960 ;
      RECT 0.048 85.632 51.632 85.728 ;
      RECT 0.048 86.400 51.632 86.496 ;
      RECT 0.048 87.168 51.632 87.264 ;
      RECT 0.048 87.936 51.632 88.032 ;
      RECT 0.048 88.704 51.632 88.800 ;
      RECT 0.048 89.472 51.632 89.568 ;
      RECT 0.048 90.240 51.632 90.336 ;
      RECT 0.048 91.008 51.632 91.104 ;
      RECT 0.048 91.776 51.632 91.872 ;
      RECT 0.048 92.544 51.632 92.640 ;
      RECT 0.048 93.312 51.632 93.408 ;
      RECT 0.048 94.080 51.632 94.176 ;
      RECT 0.048 94.848 51.632 94.944 ;
      RECT 0.048 95.616 51.632 95.712 ;
      RECT 0.048 96.384 51.632 96.480 ;
      RECT 0.048 97.152 51.632 97.248 ;
      RECT 0.048 97.920 51.632 98.016 ;
      RECT 0.048 98.688 51.632 98.784 ;
      RECT 0.048 99.456 51.632 99.552 ;
      RECT 0.048 100.224 51.632 100.320 ;
      RECT 0.048 100.992 51.632 101.088 ;
      RECT 0.048 101.760 51.632 101.856 ;
      RECT 0.048 102.528 51.632 102.624 ;
      RECT 0.048 103.296 51.632 103.392 ;
      RECT 0.048 104.064 51.632 104.160 ;
      RECT 0.048 104.832 51.632 104.928 ;
      RECT 0.048 105.600 51.632 105.696 ;
      RECT 0.048 106.368 51.632 106.464 ;
      RECT 0.048 107.136 51.632 107.232 ;
      RECT 0.048 107.904 51.632 108.000 ;
      RECT 0.048 108.672 51.632 108.768 ;
      RECT 0.048 109.440 51.632 109.536 ;
      RECT 0.048 110.208 51.632 110.304 ;
      RECT 0.048 110.976 51.632 111.072 ;
      RECT 0.048 111.744 51.632 111.840 ;
      RECT 0.048 112.512 51.632 112.608 ;
      RECT 0.048 113.280 51.632 113.376 ;
      RECT 0.048 114.048 51.632 114.144 ;
      RECT 0.048 114.816 51.632 114.912 ;
      RECT 0.048 115.584 51.632 115.680 ;
      RECT 0.048 116.352 51.632 116.448 ;
      RECT 0.048 117.120 51.632 117.216 ;
      RECT 0.048 117.888 51.632 117.984 ;
      RECT 0.048 118.656 51.632 118.752 ;
      RECT 0.048 119.424 51.632 119.520 ;
      RECT 0.048 120.192 51.632 120.288 ;
      RECT 0.048 120.960 51.632 121.056 ;
      RECT 0.048 121.728 51.632 121.824 ;
      RECT 0.048 122.496 51.632 122.592 ;
      RECT 0.048 123.264 51.632 123.360 ;
      RECT 0.048 124.032 51.632 124.128 ;
      RECT 0.048 124.800 51.632 124.896 ;
      RECT 0.048 125.568 51.632 125.664 ;
      RECT 0.048 126.336 51.632 126.432 ;
      RECT 0.048 127.104 51.632 127.200 ;
      RECT 0.048 127.872 51.632 127.968 ;
      RECT 0.048 128.640 51.632 128.736 ;
      RECT 0.048 129.408 51.632 129.504 ;
      RECT 0.048 130.176 51.632 130.272 ;
      RECT 0.048 130.944 51.632 131.040 ;
      RECT 0.048 131.712 51.632 131.808 ;
      RECT 0.048 132.480 51.632 132.576 ;
      RECT 0.048 133.248 51.632 133.344 ;
      RECT 0.048 134.016 51.632 134.112 ;
      RECT 0.048 134.784 51.632 134.880 ;
      RECT 0.048 135.552 51.632 135.648 ;
      RECT 0.048 136.320 51.632 136.416 ;
      RECT 0.048 137.088 51.632 137.184 ;
      RECT 0.048 137.856 51.632 137.952 ;
      RECT 0.048 138.624 51.632 138.720 ;
      RECT 0.048 139.392 51.632 139.488 ;
      RECT 0.048 140.160 51.632 140.256 ;
      RECT 0.048 140.928 51.632 141.024 ;
      RECT 0.048 141.696 51.632 141.792 ;
      RECT 0.048 142.464 51.632 142.560 ;
      RECT 0.048 143.232 51.632 143.328 ;
      RECT 0.048 144.000 51.632 144.096 ;
      RECT 0.048 144.768 51.632 144.864 ;
      RECT 0.048 145.536 51.632 145.632 ;
      RECT 0.048 146.304 51.632 146.400 ;
      RECT 0.048 147.072 51.632 147.168 ;
      RECT 0.048 147.840 51.632 147.936 ;
      RECT 0.048 148.608 51.632 148.704 ;
      RECT 0.048 149.376 51.632 149.472 ;
      RECT 0.048 150.144 51.632 150.240 ;
      RECT 0.048 150.912 51.632 151.008 ;
      RECT 0.048 151.680 51.632 151.776 ;
      RECT 0.048 152.448 51.632 152.544 ;
      RECT 0.048 153.216 51.632 153.312 ;
      RECT 0.048 153.984 51.632 154.080 ;
      RECT 0.048 154.752 51.632 154.848 ;
      RECT 0.048 155.520 51.632 155.616 ;
      RECT 0.048 156.288 51.632 156.384 ;
      RECT 0.048 157.056 51.632 157.152 ;
      RECT 0.048 157.824 51.632 157.920 ;
      RECT 0.048 158.592 51.632 158.688 ;
      RECT 0.048 159.360 51.632 159.456 ;
      RECT 0.048 160.128 51.632 160.224 ;
      RECT 0.048 160.896 51.632 160.992 ;
      RECT 0.048 161.664 51.632 161.760 ;
      RECT 0.048 162.432 51.632 162.528 ;
      RECT 0.048 163.200 51.632 163.296 ;
      RECT 0.048 163.968 51.632 164.064 ;
      RECT 0.048 164.736 51.632 164.832 ;
      RECT 0.048 165.504 51.632 165.600 ;
      RECT 0.048 166.272 51.632 166.368 ;
      RECT 0.048 167.040 51.632 167.136 ;
      RECT 0.048 167.808 51.632 167.904 ;
      RECT 0.048 168.576 51.632 168.672 ;
      RECT 0.048 169.344 51.632 169.440 ;
      RECT 0.048 170.112 51.632 170.208 ;
      RECT 0.048 170.880 51.632 170.976 ;
      RECT 0.048 171.648 51.632 171.744 ;
      RECT 0.048 172.416 51.632 172.512 ;
      RECT 0.048 173.184 51.632 173.280 ;
      RECT 0.048 173.952 51.632 174.048 ;
      RECT 0.048 174.720 51.632 174.816 ;
      RECT 0.048 175.488 51.632 175.584 ;
      RECT 0.048 176.256 51.632 176.352 ;
      RECT 0.048 177.024 51.632 177.120 ;
      RECT 0.048 177.792 51.632 177.888 ;
      RECT 0.048 178.560 51.632 178.656 ;
      RECT 0.048 179.328 51.632 179.424 ;
      RECT 0.048 180.096 51.632 180.192 ;
      RECT 0.048 180.864 51.632 180.960 ;
      RECT 0.048 181.632 51.632 181.728 ;
      RECT 0.048 182.400 51.632 182.496 ;
      RECT 0.048 183.168 51.632 183.264 ;
      RECT 0.048 183.936 51.632 184.032 ;
      RECT 0.048 184.704 51.632 184.800 ;
      RECT 0.048 185.472 51.632 185.568 ;
      RECT 0.048 186.240 51.632 186.336 ;
      RECT 0.048 187.008 51.632 187.104 ;
      RECT 0.048 187.776 51.632 187.872 ;
      RECT 0.048 188.544 51.632 188.640 ;
      RECT 0.048 189.312 51.632 189.408 ;
      RECT 0.048 190.080 51.632 190.176 ;
      RECT 0.048 190.848 51.632 190.944 ;
      RECT 0.048 191.616 51.632 191.712 ;
      RECT 0.048 192.384 51.632 192.480 ;
      RECT 0.048 193.152 51.632 193.248 ;
      RECT 0.048 193.920 51.632 194.016 ;
      RECT 0.048 194.688 51.632 194.784 ;
      RECT 0.048 195.456 51.632 195.552 ;
      RECT 0.048 196.224 51.632 196.320 ;
      RECT 0.048 196.992 51.632 197.088 ;
      RECT 0.048 197.760 51.632 197.856 ;
      RECT 0.048 198.528 51.632 198.624 ;
      RECT 0.048 199.296 51.632 199.392 ;
      RECT 0.048 200.064 51.632 200.160 ;
      RECT 0.048 200.832 51.632 200.928 ;
      RECT 0.048 201.600 51.632 201.696 ;
      RECT 0.048 202.368 51.632 202.464 ;
      RECT 0.048 203.136 51.632 203.232 ;
      RECT 0.048 203.904 51.632 204.000 ;
      RECT 0.048 204.672 51.632 204.768 ;
      RECT 0.048 205.440 51.632 205.536 ;
      RECT 0.048 206.208 51.632 206.304 ;
      RECT 0.048 206.976 51.632 207.072 ;
      RECT 0.048 207.744 51.632 207.840 ;
      RECT 0.048 208.512 51.632 208.608 ;
      RECT 0.048 209.280 51.632 209.376 ;
      RECT 0.048 210.048 51.632 210.144 ;
      RECT 0.048 210.816 51.632 210.912 ;
      RECT 0.048 211.584 51.632 211.680 ;
      RECT 0.048 212.352 51.632 212.448 ;
      RECT 0.048 213.120 51.632 213.216 ;
      RECT 0.048 213.888 51.632 213.984 ;
      RECT 0.048 214.656 51.632 214.752 ;
      RECT 0.048 215.424 51.632 215.520 ;
      RECT 0.048 216.192 51.632 216.288 ;
      RECT 0.048 216.960 51.632 217.056 ;
      RECT 0.048 217.728 51.632 217.824 ;
      RECT 0.048 218.496 51.632 218.592 ;
      RECT 0.048 219.264 51.632 219.360 ;
      RECT 0.048 220.032 51.632 220.128 ;
      RECT 0.048 220.800 51.632 220.896 ;
      RECT 0.048 221.568 51.632 221.664 ;
      RECT 0.048 222.336 51.632 222.432 ;
      RECT 0.048 223.104 51.632 223.200 ;
      RECT 0.048 223.872 51.632 223.968 ;
      RECT 0.048 224.640 51.632 224.736 ;
      RECT 0.048 225.408 51.632 225.504 ;
      RECT 0.048 226.176 51.632 226.272 ;
      RECT 0.048 226.944 51.632 227.040 ;
      RECT 0.048 227.712 51.632 227.808 ;
      RECT 0.048 228.480 51.632 228.576 ;
      RECT 0.048 229.248 51.632 229.344 ;
      RECT 0.048 230.016 51.632 230.112 ;
      RECT 0.048 230.784 51.632 230.880 ;
      RECT 0.048 231.552 51.632 231.648 ;
      RECT 0.048 232.320 51.632 232.416 ;
      RECT 0.048 233.088 51.632 233.184 ;
      RECT 0.048 233.856 51.632 233.952 ;
      RECT 0.048 234.624 51.632 234.720 ;
      RECT 0.048 235.392 51.632 235.488 ;
      RECT 0.048 236.160 51.632 236.256 ;
      RECT 0.048 236.928 51.632 237.024 ;
      RECT 0.048 237.696 51.632 237.792 ;
      RECT 0.048 238.464 51.632 238.560 ;
      RECT 0.048 239.232 51.632 239.328 ;
      RECT 0.048 240.000 51.632 240.096 ;
      RECT 0.048 240.768 51.632 240.864 ;
      RECT 0.048 241.536 51.632 241.632 ;
      RECT 0.048 242.304 51.632 242.400 ;
      RECT 0.048 243.072 51.632 243.168 ;
      RECT 0.048 243.840 51.632 243.936 ;
      RECT 0.048 244.608 51.632 244.704 ;
      RECT 0.048 245.376 51.632 245.472 ;
      RECT 0.048 246.144 51.632 246.240 ;
      RECT 0.048 246.912 51.632 247.008 ;
      RECT 0.048 247.680 51.632 247.776 ;
      RECT 0.048 248.448 51.632 248.544 ;
      RECT 0.048 249.216 51.632 249.312 ;
      RECT 0.048 249.984 51.632 250.080 ;
      RECT 0.048 250.752 51.632 250.848 ;
      RECT 0.048 251.520 51.632 251.616 ;
      RECT 0.048 252.288 51.632 252.384 ;
      RECT 0.048 253.056 51.632 253.152 ;
      RECT 0.048 253.824 51.632 253.920 ;
      RECT 0.048 254.592 51.632 254.688 ;
      RECT 0.048 255.360 51.632 255.456 ;
      RECT 0.048 256.128 51.632 256.224 ;
      RECT 0.048 256.896 51.632 256.992 ;
      RECT 0.048 257.664 51.632 257.760 ;
      RECT 0.048 258.432 51.632 258.528 ;
      RECT 0.048 259.200 51.632 259.296 ;
      RECT 0.048 259.968 51.632 260.064 ;
      RECT 0.048 260.736 51.632 260.832 ;
      RECT 0.048 261.504 51.632 261.600 ;
      RECT 0.048 262.272 51.632 262.368 ;
      RECT 0.048 263.040 51.632 263.136 ;
      RECT 0.048 263.808 51.632 263.904 ;
      RECT 0.048 264.576 51.632 264.672 ;
      RECT 0.048 265.344 51.632 265.440 ;
      RECT 0.048 266.112 51.632 266.208 ;
      RECT 0.048 266.880 51.632 266.976 ;
      RECT 0.048 267.648 51.632 267.744 ;
      RECT 0.048 268.416 51.632 268.512 ;
      RECT 0.048 269.184 51.632 269.280 ;
      RECT 0.048 269.952 51.632 270.048 ;
      RECT 0.048 270.720 51.632 270.816 ;
      RECT 0.048 271.488 51.632 271.584 ;
      RECT 0.048 272.256 51.632 272.352 ;
      RECT 0.048 273.024 51.632 273.120 ;
      RECT 0.048 273.792 51.632 273.888 ;
      RECT 0.048 274.560 51.632 274.656 ;
      RECT 0.048 275.328 51.632 275.424 ;
      RECT 0.048 276.096 51.632 276.192 ;
      RECT 0.048 276.864 51.632 276.960 ;
      RECT 0.048 277.632 51.632 277.728 ;
      RECT 0.048 278.400 51.632 278.496 ;
      RECT 0.048 279.168 51.632 279.264 ;
      RECT 0.048 279.936 51.632 280.032 ;
      RECT 0.048 280.704 51.632 280.800 ;
      RECT 0.048 281.472 51.632 281.568 ;
      RECT 0.048 282.240 51.632 282.336 ;
      RECT 0.048 283.008 51.632 283.104 ;
      RECT 0.048 283.776 51.632 283.872 ;
      RECT 0.048 284.544 51.632 284.640 ;
      RECT 0.048 285.312 51.632 285.408 ;
      RECT 0.048 286.080 51.632 286.176 ;
      RECT 0.048 286.848 51.632 286.944 ;
      RECT 0.048 287.616 51.632 287.712 ;
      RECT 0.048 288.384 51.632 288.480 ;
      RECT 0.048 289.152 51.632 289.248 ;
      RECT 0.048 289.920 51.632 290.016 ;
      RECT 0.048 290.688 51.632 290.784 ;
      RECT 0.048 291.456 51.632 291.552 ;
      RECT 0.048 292.224 51.632 292.320 ;
      RECT 0.048 292.992 51.632 293.088 ;
      RECT 0.048 293.760 51.632 293.856 ;
      RECT 0.048 294.528 51.632 294.624 ;
      RECT 0.048 295.296 51.632 295.392 ;
      RECT 0.048 296.064 51.632 296.160 ;
      RECT 0.048 296.832 51.632 296.928 ;
      RECT 0.048 297.600 51.632 297.696 ;
      RECT 0.048 298.368 51.632 298.464 ;
      RECT 0.048 299.136 51.632 299.232 ;
      RECT 0.048 299.904 51.632 300.000 ;
      RECT 0.048 300.672 51.632 300.768 ;
      RECT 0.048 301.440 51.632 301.536 ;
      RECT 0.048 302.208 51.632 302.304 ;
      RECT 0.048 302.976 51.632 303.072 ;
      RECT 0.048 303.744 51.632 303.840 ;
      RECT 0.048 304.512 51.632 304.608 ;
      RECT 0.048 305.280 51.632 305.376 ;
      RECT 0.048 306.048 51.632 306.144 ;
      RECT 0.048 306.816 51.632 306.912 ;
      RECT 0.048 307.584 51.632 307.680 ;
      RECT 0.048 308.352 51.632 308.448 ;
      RECT 0.048 309.120 51.632 309.216 ;
      RECT 0.048 309.888 51.632 309.984 ;
      RECT 0.048 310.656 51.632 310.752 ;
      RECT 0.048 311.424 51.632 311.520 ;
      RECT 0.048 312.192 51.632 312.288 ;
      RECT 0.048 312.960 51.632 313.056 ;
      RECT 0.048 313.728 51.632 313.824 ;
      RECT 0.048 314.496 51.632 314.592 ;
      RECT 0.048 315.264 51.632 315.360 ;
      RECT 0.048 316.032 51.632 316.128 ;
      RECT 0.048 316.800 51.632 316.896 ;
      RECT 0.048 317.568 51.632 317.664 ;
      RECT 0.048 318.336 51.632 318.432 ;
      RECT 0.048 319.104 51.632 319.200 ;
      RECT 0.048 319.872 51.632 319.968 ;
      RECT 0.048 320.640 51.632 320.736 ;
      RECT 0.048 321.408 51.632 321.504 ;
      RECT 0.048 322.176 51.632 322.272 ;
      RECT 0.048 322.944 51.632 323.040 ;
      RECT 0.048 323.712 51.632 323.808 ;
      RECT 0.048 324.480 51.632 324.576 ;
      RECT 0.048 325.248 51.632 325.344 ;
      RECT 0.048 326.016 51.632 326.112 ;
      RECT 0.048 326.784 51.632 326.880 ;
      RECT 0.048 327.552 51.632 327.648 ;
      RECT 0.048 328.320 51.632 328.416 ;
      RECT 0.048 329.088 51.632 329.184 ;
      RECT 0.048 329.856 51.632 329.952 ;
      RECT 0.048 330.624 51.632 330.720 ;
      RECT 0.048 331.392 51.632 331.488 ;
      RECT 0.048 332.160 51.632 332.256 ;
      RECT 0.048 332.928 51.632 333.024 ;
      RECT 0.048 333.696 51.632 333.792 ;
      RECT 0.048 334.464 51.632 334.560 ;
      RECT 0.048 335.232 51.632 335.328 ;
      RECT 0.048 336.000 51.632 336.096 ;
      RECT 0.048 336.768 51.632 336.864 ;
      RECT 0.048 337.536 51.632 337.632 ;
      RECT 0.048 338.304 51.632 338.400 ;
      RECT 0.048 339.072 51.632 339.168 ;
      RECT 0.048 339.840 51.632 339.936 ;
      RECT 0.048 340.608 51.632 340.704 ;
      RECT 0.048 341.376 51.632 341.472 ;
      RECT 0.048 342.144 51.632 342.240 ;
      RECT 0.048 342.912 51.632 343.008 ;
      RECT 0.048 343.680 51.632 343.776 ;
      RECT 0.048 344.448 51.632 344.544 ;
      RECT 0.048 345.216 51.632 345.312 ;
      RECT 0.048 345.984 51.632 346.080 ;
      RECT 0.048 346.752 51.632 346.848 ;
      RECT 0.048 347.520 51.632 347.616 ;
      RECT 0.048 348.288 51.632 348.384 ;
      RECT 0.048 349.056 51.632 349.152 ;
      RECT 0.048 349.824 51.632 349.920 ;
      RECT 0.048 350.592 51.632 350.688 ;
      RECT 0.048 351.360 51.632 351.456 ;
      RECT 0.048 352.128 51.632 352.224 ;
      RECT 0.048 352.896 51.632 352.992 ;
      RECT 0.048 353.664 51.632 353.760 ;
      RECT 0.048 354.432 51.632 354.528 ;
      RECT 0.048 355.200 51.632 355.296 ;
      RECT 0.048 355.968 51.632 356.064 ;
      RECT 0.048 356.736 51.632 356.832 ;
      RECT 0.048 357.504 51.632 357.600 ;
      RECT 0.048 358.272 51.632 358.368 ;
      RECT 0.048 359.040 51.632 359.136 ;
      RECT 0.048 359.808 51.632 359.904 ;
      RECT 0.048 360.576 51.632 360.672 ;
      RECT 0.048 361.344 51.632 361.440 ;
      RECT 0.048 362.112 51.632 362.208 ;
      RECT 0.048 362.880 51.632 362.976 ;
      RECT 0.048 363.648 51.632 363.744 ;
      RECT 0.048 364.416 51.632 364.512 ;
      RECT 0.048 365.184 51.632 365.280 ;
    END
  END VDD
  OBS
    LAYER M1 ;
    RECT 0 0 51.680 365.400 ;
    LAYER M2 ;
    RECT 0 0 51.680 365.400 ;
    LAYER M3 ;
    RECT 0 0 51.680 365.400 ;
    LAYER M4 ;
    RECT 0 0 51.680 365.400 ;
  END
END fakeram7_tdp_8192x32

END LIBRARY
